VERSION 5.7 ;
BUSBITCHARS "[]" ;
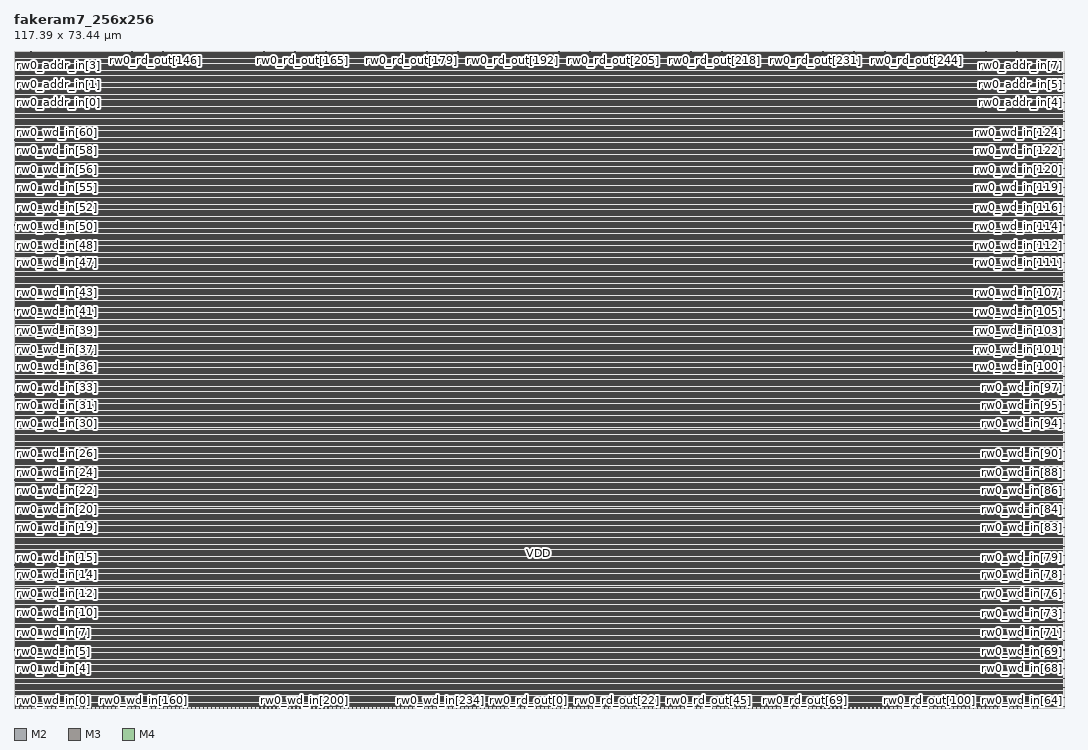
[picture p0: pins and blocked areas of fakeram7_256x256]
MACRO fakeram7_256x256
  FOREIGN fakeram7_256x256 0 0 ;
  SYMMETRY X Y R90 ;
  SIZE 117.390 BY 73.440 ;
  CLASS BLOCK ;
  PIN rw0_wd_in[0]
    DIRECTION INPUT ;
    USE SIGNAL ;
    SHAPE ABUTMENT ;
    PORT
      LAYER M2 ;
      RECT 0.000 0.138 0.036 0.150 ;
    END
  END rw0_wd_in[0]
  PIN rw0_wd_in[1]
    DIRECTION INPUT ;
    USE SIGNAL ;
    SHAPE ABUTMENT ;
    PORT
      LAYER M2 ;
      RECT 0.000 1.194 0.036 1.206 ;
    END
  END rw0_wd_in[1]
  PIN rw0_wd_in[2]
    DIRECTION INPUT ;
    USE SIGNAL ;
    SHAPE ABUTMENT ;
    PORT
      LAYER M2 ;
      RECT 0.000 2.250 0.036 2.262 ;
    END
  END rw0_wd_in[2]
  PIN rw0_wd_in[3]
    DIRECTION INPUT ;
    USE SIGNAL ;
    SHAPE ABUTMENT ;
    PORT
      LAYER M2 ;
      RECT 0.000 3.306 0.036 3.318 ;
    END
  END rw0_wd_in[3]
  PIN rw0_wd_in[4]
    DIRECTION INPUT ;
    USE SIGNAL ;
    SHAPE ABUTMENT ;
    PORT
      LAYER M2 ;
      RECT 0.000 4.362 0.036 4.374 ;
    END
  END rw0_wd_in[4]
  PIN rw0_wd_in[5]
    DIRECTION INPUT ;
    USE SIGNAL ;
    SHAPE ABUTMENT ;
    PORT
      LAYER M2 ;
      RECT 0.000 5.418 0.036 5.430 ;
    END
  END rw0_wd_in[5]
  PIN rw0_wd_in[6]
    DIRECTION INPUT ;
    USE SIGNAL ;
    SHAPE ABUTMENT ;
    PORT
      LAYER M2 ;
      RECT 0.000 6.474 0.036 6.486 ;
    END
  END rw0_wd_in[6]
  PIN rw0_wd_in[7]
    DIRECTION INPUT ;
    USE SIGNAL ;
    SHAPE ABUTMENT ;
    PORT
      LAYER M2 ;
      RECT 0.000 7.530 0.036 7.542 ;
    END
  END rw0_wd_in[7]
  PIN rw0_wd_in[8]
    DIRECTION INPUT ;
    USE SIGNAL ;
    SHAPE ABUTMENT ;
    PORT
      LAYER M2 ;
      RECT 0.000 8.586 0.036 8.598 ;
    END
  END rw0_wd_in[8]
  PIN rw0_wd_in[9]
    DIRECTION INPUT ;
    USE SIGNAL ;
    SHAPE ABUTMENT ;
    PORT
      LAYER M2 ;
      RECT 0.000 9.642 0.036 9.654 ;
    END
  END rw0_wd_in[9]
  PIN rw0_wd_in[10]
    DIRECTION INPUT ;
    USE SIGNAL ;
    SHAPE ABUTMENT ;
    PORT
      LAYER M2 ;
      RECT 0.000 10.698 0.036 10.710 ;
    END
  END rw0_wd_in[10]
  PIN rw0_wd_in[11]
    DIRECTION INPUT ;
    USE SIGNAL ;
    SHAPE ABUTMENT ;
    PORT
      LAYER M2 ;
      RECT 0.000 11.754 0.036 11.766 ;
    END
  END rw0_wd_in[11]
  PIN rw0_wd_in[12]
    DIRECTION INPUT ;
    USE SIGNAL ;
    SHAPE ABUTMENT ;
    PORT
      LAYER M2 ;
      RECT 0.000 12.810 0.036 12.822 ;
    END
  END rw0_wd_in[12]
  PIN rw0_wd_in[13]
    DIRECTION INPUT ;
    USE SIGNAL ;
    SHAPE ABUTMENT ;
    PORT
      LAYER M2 ;
      RECT 0.000 13.866 0.036 13.878 ;
    END
  END rw0_wd_in[13]
  PIN rw0_wd_in[14]
    DIRECTION INPUT ;
    USE SIGNAL ;
    SHAPE ABUTMENT ;
    PORT
      LAYER M2 ;
      RECT 0.000 14.922 0.036 14.934 ;
    END
  END rw0_wd_in[14]
  PIN rw0_wd_in[15]
    DIRECTION INPUT ;
    USE SIGNAL ;
    SHAPE ABUTMENT ;
    PORT
      LAYER M2 ;
      RECT 0.000 15.978 0.036 15.990 ;
    END
  END rw0_wd_in[15]
  PIN rw0_wd_in[16]
    DIRECTION INPUT ;
    USE SIGNAL ;
    SHAPE ABUTMENT ;
    PORT
      LAYER M2 ;
      RECT 0.000 17.034 0.036 17.046 ;
    END
  END rw0_wd_in[16]
  PIN rw0_wd_in[17]
    DIRECTION INPUT ;
    USE SIGNAL ;
    SHAPE ABUTMENT ;
    PORT
      LAYER M2 ;
      RECT 0.000 18.090 0.036 18.102 ;
    END
  END rw0_wd_in[17]
  PIN rw0_wd_in[18]
    DIRECTION INPUT ;
    USE SIGNAL ;
    SHAPE ABUTMENT ;
    PORT
      LAYER M2 ;
      RECT 0.000 19.146 0.036 19.158 ;
    END
  END rw0_wd_in[18]
  PIN rw0_wd_in[19]
    DIRECTION INPUT ;
    USE SIGNAL ;
    SHAPE ABUTMENT ;
    PORT
      LAYER M2 ;
      RECT 0.000 20.202 0.036 20.214 ;
    END
  END rw0_wd_in[19]
  PIN rw0_wd_in[20]
    DIRECTION INPUT ;
    USE SIGNAL ;
    SHAPE ABUTMENT ;
    PORT
      LAYER M2 ;
      RECT 0.000 21.258 0.036 21.270 ;
    END
  END rw0_wd_in[20]
  PIN rw0_wd_in[21]
    DIRECTION INPUT ;
    USE SIGNAL ;
    SHAPE ABUTMENT ;
    PORT
      LAYER M2 ;
      RECT 0.000 22.314 0.036 22.326 ;
    END
  END rw0_wd_in[21]
  PIN rw0_wd_in[22]
    DIRECTION INPUT ;
    USE SIGNAL ;
    SHAPE ABUTMENT ;
    PORT
      LAYER M2 ;
      RECT 0.000 23.370 0.036 23.382 ;
    END
  END rw0_wd_in[22]
  PIN rw0_wd_in[23]
    DIRECTION INPUT ;
    USE SIGNAL ;
    SHAPE ABUTMENT ;
    PORT
      LAYER M2 ;
      RECT 0.000 24.426 0.036 24.438 ;
    END
  END rw0_wd_in[23]
  PIN rw0_wd_in[24]
    DIRECTION INPUT ;
    USE SIGNAL ;
    SHAPE ABUTMENT ;
    PORT
      LAYER M2 ;
      RECT 0.000 25.482 0.036 25.494 ;
    END
  END rw0_wd_in[24]
  PIN rw0_wd_in[25]
    DIRECTION INPUT ;
    USE SIGNAL ;
    SHAPE ABUTMENT ;
    PORT
      LAYER M2 ;
      RECT 0.000 26.538 0.036 26.550 ;
    END
  END rw0_wd_in[25]
  PIN rw0_wd_in[26]
    DIRECTION INPUT ;
    USE SIGNAL ;
    SHAPE ABUTMENT ;
    PORT
      LAYER M2 ;
      RECT 0.000 27.594 0.036 27.606 ;
    END
  END rw0_wd_in[26]
  PIN rw0_wd_in[27]
    DIRECTION INPUT ;
    USE SIGNAL ;
    SHAPE ABUTMENT ;
    PORT
      LAYER M2 ;
      RECT 0.000 28.650 0.036 28.662 ;
    END
  END rw0_wd_in[27]
  PIN rw0_wd_in[28]
    DIRECTION INPUT ;
    USE SIGNAL ;
    SHAPE ABUTMENT ;
    PORT
      LAYER M2 ;
      RECT 0.000 29.706 0.036 29.718 ;
    END
  END rw0_wd_in[28]
  PIN rw0_wd_in[29]
    DIRECTION INPUT ;
    USE SIGNAL ;
    SHAPE ABUTMENT ;
    PORT
      LAYER M2 ;
      RECT 0.000 30.762 0.036 30.774 ;
    END
  END rw0_wd_in[29]
  PIN rw0_wd_in[30]
    DIRECTION INPUT ;
    USE SIGNAL ;
    SHAPE ABUTMENT ;
    PORT
      LAYER M2 ;
      RECT 0.000 31.818 0.036 31.830 ;
    END
  END rw0_wd_in[30]
  PIN rw0_wd_in[31]
    DIRECTION INPUT ;
    USE SIGNAL ;
    SHAPE ABUTMENT ;
    PORT
      LAYER M2 ;
      RECT 0.000 32.874 0.036 32.886 ;
    END
  END rw0_wd_in[31]
  PIN rw0_wd_in[32]
    DIRECTION INPUT ;
    USE SIGNAL ;
    SHAPE ABUTMENT ;
    PORT
      LAYER M2 ;
      RECT 0.000 33.930 0.036 33.942 ;
    END
  END rw0_wd_in[32]
  PIN rw0_wd_in[33]
    DIRECTION INPUT ;
    USE SIGNAL ;
    SHAPE ABUTMENT ;
    PORT
      LAYER M2 ;
      RECT 0.000 34.986 0.036 34.998 ;
    END
  END rw0_wd_in[33]
  PIN rw0_wd_in[34]
    DIRECTION INPUT ;
    USE SIGNAL ;
    SHAPE ABUTMENT ;
    PORT
      LAYER M2 ;
      RECT 0.000 36.042 0.036 36.054 ;
    END
  END rw0_wd_in[34]
  PIN rw0_wd_in[35]
    DIRECTION INPUT ;
    USE SIGNAL ;
    SHAPE ABUTMENT ;
    PORT
      LAYER M2 ;
      RECT 0.000 37.098 0.036 37.110 ;
    END
  END rw0_wd_in[35]
  PIN rw0_wd_in[36]
    DIRECTION INPUT ;
    USE SIGNAL ;
    SHAPE ABUTMENT ;
    PORT
      LAYER M2 ;
      RECT 0.000 38.154 0.036 38.166 ;
    END
  END rw0_wd_in[36]
  PIN rw0_wd_in[37]
    DIRECTION INPUT ;
    USE SIGNAL ;
    SHAPE ABUTMENT ;
    PORT
      LAYER M2 ;
      RECT 0.000 39.210 0.036 39.222 ;
    END
  END rw0_wd_in[37]
  PIN rw0_wd_in[38]
    DIRECTION INPUT ;
    USE SIGNAL ;
    SHAPE ABUTMENT ;
    PORT
      LAYER M2 ;
      RECT 0.000 40.266 0.036 40.278 ;
    END
  END rw0_wd_in[38]
  PIN rw0_wd_in[39]
    DIRECTION INPUT ;
    USE SIGNAL ;
    SHAPE ABUTMENT ;
    PORT
      LAYER M2 ;
      RECT 0.000 41.322 0.036 41.334 ;
    END
  END rw0_wd_in[39]
  PIN rw0_wd_in[40]
    DIRECTION INPUT ;
    USE SIGNAL ;
    SHAPE ABUTMENT ;
    PORT
      LAYER M2 ;
      RECT 0.000 42.378 0.036 42.390 ;
    END
  END rw0_wd_in[40]
  PIN rw0_wd_in[41]
    DIRECTION INPUT ;
    USE SIGNAL ;
    SHAPE ABUTMENT ;
    PORT
      LAYER M2 ;
      RECT 0.000 43.434 0.036 43.446 ;
    END
  END rw0_wd_in[41]
  PIN rw0_wd_in[42]
    DIRECTION INPUT ;
    USE SIGNAL ;
    SHAPE ABUTMENT ;
    PORT
      LAYER M2 ;
      RECT 0.000 44.490 0.036 44.502 ;
    END
  END rw0_wd_in[42]
  PIN rw0_wd_in[43]
    DIRECTION INPUT ;
    USE SIGNAL ;
    SHAPE ABUTMENT ;
    PORT
      LAYER M2 ;
      RECT 0.000 45.546 0.036 45.558 ;
    END
  END rw0_wd_in[43]
  PIN rw0_wd_in[44]
    DIRECTION INPUT ;
    USE SIGNAL ;
    SHAPE ABUTMENT ;
    PORT
      LAYER M2 ;
      RECT 0.000 46.602 0.036 46.614 ;
    END
  END rw0_wd_in[44]
  PIN rw0_wd_in[45]
    DIRECTION INPUT ;
    USE SIGNAL ;
    SHAPE ABUTMENT ;
    PORT
      LAYER M2 ;
      RECT 0.000 47.658 0.036 47.670 ;
    END
  END rw0_wd_in[45]
  PIN rw0_wd_in[46]
    DIRECTION INPUT ;
    USE SIGNAL ;
    SHAPE ABUTMENT ;
    PORT
      LAYER M2 ;
      RECT 0.000 48.714 0.036 48.726 ;
    END
  END rw0_wd_in[46]
  PIN rw0_wd_in[47]
    DIRECTION INPUT ;
    USE SIGNAL ;
    SHAPE ABUTMENT ;
    PORT
      LAYER M2 ;
      RECT 0.000 49.770 0.036 49.782 ;
    END
  END rw0_wd_in[47]
  PIN rw0_wd_in[48]
    DIRECTION INPUT ;
    USE SIGNAL ;
    SHAPE ABUTMENT ;
    PORT
      LAYER M2 ;
      RECT 0.000 50.826 0.036 50.838 ;
    END
  END rw0_wd_in[48]
  PIN rw0_wd_in[49]
    DIRECTION INPUT ;
    USE SIGNAL ;
    SHAPE ABUTMENT ;
    PORT
      LAYER M2 ;
      RECT 0.000 51.882 0.036 51.894 ;
    END
  END rw0_wd_in[49]
  PIN rw0_wd_in[50]
    DIRECTION INPUT ;
    USE SIGNAL ;
    SHAPE ABUTMENT ;
    PORT
      LAYER M2 ;
      RECT 0.000 52.938 0.036 52.950 ;
    END
  END rw0_wd_in[50]
  PIN rw0_wd_in[51]
    DIRECTION INPUT ;
    USE SIGNAL ;
    SHAPE ABUTMENT ;
    PORT
      LAYER M2 ;
      RECT 0.000 53.994 0.036 54.006 ;
    END
  END rw0_wd_in[51]
  PIN rw0_wd_in[52]
    DIRECTION INPUT ;
    USE SIGNAL ;
    SHAPE ABUTMENT ;
    PORT
      LAYER M2 ;
      RECT 0.000 55.050 0.036 55.062 ;
    END
  END rw0_wd_in[52]
  PIN rw0_wd_in[53]
    DIRECTION INPUT ;
    USE SIGNAL ;
    SHAPE ABUTMENT ;
    PORT
      LAYER M2 ;
      RECT 0.000 56.106 0.036 56.118 ;
    END
  END rw0_wd_in[53]
  PIN rw0_wd_in[54]
    DIRECTION INPUT ;
    USE SIGNAL ;
    SHAPE ABUTMENT ;
    PORT
      LAYER M2 ;
      RECT 0.000 57.162 0.036 57.174 ;
    END
  END rw0_wd_in[54]
  PIN rw0_wd_in[55]
    DIRECTION INPUT ;
    USE SIGNAL ;
    SHAPE ABUTMENT ;
    PORT
      LAYER M2 ;
      RECT 0.000 58.218 0.036 58.230 ;
    END
  END rw0_wd_in[55]
  PIN rw0_wd_in[56]
    DIRECTION INPUT ;
    USE SIGNAL ;
    SHAPE ABUTMENT ;
    PORT
      LAYER M2 ;
      RECT 0.000 59.274 0.036 59.286 ;
    END
  END rw0_wd_in[56]
  PIN rw0_wd_in[57]
    DIRECTION INPUT ;
    USE SIGNAL ;
    SHAPE ABUTMENT ;
    PORT
      LAYER M2 ;
      RECT 0.000 60.330 0.036 60.342 ;
    END
  END rw0_wd_in[57]
  PIN rw0_wd_in[58]
    DIRECTION INPUT ;
    USE SIGNAL ;
    SHAPE ABUTMENT ;
    PORT
      LAYER M2 ;
      RECT 0.000 61.386 0.036 61.398 ;
    END
  END rw0_wd_in[58]
  PIN rw0_wd_in[59]
    DIRECTION INPUT ;
    USE SIGNAL ;
    SHAPE ABUTMENT ;
    PORT
      LAYER M2 ;
      RECT 0.000 62.442 0.036 62.454 ;
    END
  END rw0_wd_in[59]
  PIN rw0_wd_in[60]
    DIRECTION INPUT ;
    USE SIGNAL ;
    SHAPE ABUTMENT ;
    PORT
      LAYER M2 ;
      RECT 0.000 63.498 0.036 63.510 ;
    END
  END rw0_wd_in[60]
  PIN rw0_wd_in[61]
    DIRECTION INPUT ;
    USE SIGNAL ;
    SHAPE ABUTMENT ;
    PORT
      LAYER M2 ;
      RECT 0.000 64.554 0.036 64.566 ;
    END
  END rw0_wd_in[61]
  PIN rw0_wd_in[62]
    DIRECTION INPUT ;
    USE SIGNAL ;
    SHAPE ABUTMENT ;
    PORT
      LAYER M2 ;
      RECT 0.000 65.610 0.036 65.622 ;
    END
  END rw0_wd_in[62]
  PIN rw0_wd_in[63]
    DIRECTION INPUT ;
    USE SIGNAL ;
    SHAPE ABUTMENT ;
    PORT
      LAYER M2 ;
      RECT 0.000 66.666 0.036 66.678 ;
    END
  END rw0_wd_in[63]
  PIN rw0_wd_in[64]
    DIRECTION INPUT ;
    USE SIGNAL ;
    SHAPE ABUTMENT ;
    PORT
      LAYER M2 ;
      RECT 117.354 0.138 117.390 0.150 ;
    END
  END rw0_wd_in[64]
  PIN rw0_wd_in[65]
    DIRECTION INPUT ;
    USE SIGNAL ;
    SHAPE ABUTMENT ;
    PORT
      LAYER M2 ;
      RECT 117.354 1.194 117.390 1.206 ;
    END
  END rw0_wd_in[65]
  PIN rw0_wd_in[66]
    DIRECTION INPUT ;
    USE SIGNAL ;
    SHAPE ABUTMENT ;
    PORT
      LAYER M2 ;
      RECT 117.354 2.250 117.390 2.262 ;
    END
  END rw0_wd_in[66]
  PIN rw0_wd_in[67]
    DIRECTION INPUT ;
    USE SIGNAL ;
    SHAPE ABUTMENT ;
    PORT
      LAYER M2 ;
      RECT 117.354 3.306 117.390 3.318 ;
    END
  END rw0_wd_in[67]
  PIN rw0_wd_in[68]
    DIRECTION INPUT ;
    USE SIGNAL ;
    SHAPE ABUTMENT ;
    PORT
      LAYER M2 ;
      RECT 117.354 4.362 117.390 4.374 ;
    END
  END rw0_wd_in[68]
  PIN rw0_wd_in[69]
    DIRECTION INPUT ;
    USE SIGNAL ;
    SHAPE ABUTMENT ;
    PORT
      LAYER M2 ;
      RECT 117.354 5.418 117.390 5.430 ;
    END
  END rw0_wd_in[69]
  PIN rw0_wd_in[70]
    DIRECTION INPUT ;
    USE SIGNAL ;
    SHAPE ABUTMENT ;
    PORT
      LAYER M2 ;
      RECT 117.354 6.474 117.390 6.486 ;
    END
  END rw0_wd_in[70]
  PIN rw0_wd_in[71]
    DIRECTION INPUT ;
    USE SIGNAL ;
    SHAPE ABUTMENT ;
    PORT
      LAYER M2 ;
      RECT 117.354 7.530 117.390 7.542 ;
    END
  END rw0_wd_in[71]
  PIN rw0_wd_in[72]
    DIRECTION INPUT ;
    USE SIGNAL ;
    SHAPE ABUTMENT ;
    PORT
      LAYER M2 ;
      RECT 117.354 8.586 117.390 8.598 ;
    END
  END rw0_wd_in[72]
  PIN rw0_wd_in[73]
    DIRECTION INPUT ;
    USE SIGNAL ;
    SHAPE ABUTMENT ;
    PORT
      LAYER M2 ;
      RECT 117.354 9.642 117.390 9.654 ;
    END
  END rw0_wd_in[73]
  PIN rw0_wd_in[74]
    DIRECTION INPUT ;
    USE SIGNAL ;
    SHAPE ABUTMENT ;
    PORT
      LAYER M2 ;
      RECT 117.354 10.698 117.390 10.710 ;
    END
  END rw0_wd_in[74]
  PIN rw0_wd_in[75]
    DIRECTION INPUT ;
    USE SIGNAL ;
    SHAPE ABUTMENT ;
    PORT
      LAYER M2 ;
      RECT 117.354 11.754 117.390 11.766 ;
    END
  END rw0_wd_in[75]
  PIN rw0_wd_in[76]
    DIRECTION INPUT ;
    USE SIGNAL ;
    SHAPE ABUTMENT ;
    PORT
      LAYER M2 ;
      RECT 117.354 12.810 117.390 12.822 ;
    END
  END rw0_wd_in[76]
  PIN rw0_wd_in[77]
    DIRECTION INPUT ;
    USE SIGNAL ;
    SHAPE ABUTMENT ;
    PORT
      LAYER M2 ;
      RECT 117.354 13.866 117.390 13.878 ;
    END
  END rw0_wd_in[77]
  PIN rw0_wd_in[78]
    DIRECTION INPUT ;
    USE SIGNAL ;
    SHAPE ABUTMENT ;
    PORT
      LAYER M2 ;
      RECT 117.354 14.922 117.390 14.934 ;
    END
  END rw0_wd_in[78]
  PIN rw0_wd_in[79]
    DIRECTION INPUT ;
    USE SIGNAL ;
    SHAPE ABUTMENT ;
    PORT
      LAYER M2 ;
      RECT 117.354 15.978 117.390 15.990 ;
    END
  END rw0_wd_in[79]
  PIN rw0_wd_in[80]
    DIRECTION INPUT ;
    USE SIGNAL ;
    SHAPE ABUTMENT ;
    PORT
      LAYER M2 ;
      RECT 117.354 17.034 117.390 17.046 ;
    END
  END rw0_wd_in[80]
  PIN rw0_wd_in[81]
    DIRECTION INPUT ;
    USE SIGNAL ;
    SHAPE ABUTMENT ;
    PORT
      LAYER M2 ;
      RECT 117.354 18.090 117.390 18.102 ;
    END
  END rw0_wd_in[81]
  PIN rw0_wd_in[82]
    DIRECTION INPUT ;
    USE SIGNAL ;
    SHAPE ABUTMENT ;
    PORT
      LAYER M2 ;
      RECT 117.354 19.146 117.390 19.158 ;
    END
  END rw0_wd_in[82]
  PIN rw0_wd_in[83]
    DIRECTION INPUT ;
    USE SIGNAL ;
    SHAPE ABUTMENT ;
    PORT
      LAYER M2 ;
      RECT 117.354 20.202 117.390 20.214 ;
    END
  END rw0_wd_in[83]
  PIN rw0_wd_in[84]
    DIRECTION INPUT ;
    USE SIGNAL ;
    SHAPE ABUTMENT ;
    PORT
      LAYER M2 ;
      RECT 117.354 21.258 117.390 21.270 ;
    END
  END rw0_wd_in[84]
  PIN rw0_wd_in[85]
    DIRECTION INPUT ;
    USE SIGNAL ;
    SHAPE ABUTMENT ;
    PORT
      LAYER M2 ;
      RECT 117.354 22.314 117.390 22.326 ;
    END
  END rw0_wd_in[85]
  PIN rw0_wd_in[86]
    DIRECTION INPUT ;
    USE SIGNAL ;
    SHAPE ABUTMENT ;
    PORT
      LAYER M2 ;
      RECT 117.354 23.370 117.390 23.382 ;
    END
  END rw0_wd_in[86]
  PIN rw0_wd_in[87]
    DIRECTION INPUT ;
    USE SIGNAL ;
    SHAPE ABUTMENT ;
    PORT
      LAYER M2 ;
      RECT 117.354 24.426 117.390 24.438 ;
    END
  END rw0_wd_in[87]
  PIN rw0_wd_in[88]
    DIRECTION INPUT ;
    USE SIGNAL ;
    SHAPE ABUTMENT ;
    PORT
      LAYER M2 ;
      RECT 117.354 25.482 117.390 25.494 ;
    END
  END rw0_wd_in[88]
  PIN rw0_wd_in[89]
    DIRECTION INPUT ;
    USE SIGNAL ;
    SHAPE ABUTMENT ;
    PORT
      LAYER M2 ;
      RECT 117.354 26.538 117.390 26.550 ;
    END
  END rw0_wd_in[89]
  PIN rw0_wd_in[90]
    DIRECTION INPUT ;
    USE SIGNAL ;
    SHAPE ABUTMENT ;
    PORT
      LAYER M2 ;
      RECT 117.354 27.594 117.390 27.606 ;
    END
  END rw0_wd_in[90]
  PIN rw0_wd_in[91]
    DIRECTION INPUT ;
    USE SIGNAL ;
    SHAPE ABUTMENT ;
    PORT
      LAYER M2 ;
      RECT 117.354 28.650 117.390 28.662 ;
    END
  END rw0_wd_in[91]
  PIN rw0_wd_in[92]
    DIRECTION INPUT ;
    USE SIGNAL ;
    SHAPE ABUTMENT ;
    PORT
      LAYER M2 ;
      RECT 117.354 29.706 117.390 29.718 ;
    END
  END rw0_wd_in[92]
  PIN rw0_wd_in[93]
    DIRECTION INPUT ;
    USE SIGNAL ;
    SHAPE ABUTMENT ;
    PORT
      LAYER M2 ;
      RECT 117.354 30.762 117.390 30.774 ;
    END
  END rw0_wd_in[93]
  PIN rw0_wd_in[94]
    DIRECTION INPUT ;
    USE SIGNAL ;
    SHAPE ABUTMENT ;
    PORT
      LAYER M2 ;
      RECT 117.354 31.818 117.390 31.830 ;
    END
  END rw0_wd_in[94]
  PIN rw0_wd_in[95]
    DIRECTION INPUT ;
    USE SIGNAL ;
    SHAPE ABUTMENT ;
    PORT
      LAYER M2 ;
      RECT 117.354 32.874 117.390 32.886 ;
    END
  END rw0_wd_in[95]
  PIN rw0_wd_in[96]
    DIRECTION INPUT ;
    USE SIGNAL ;
    SHAPE ABUTMENT ;
    PORT
      LAYER M2 ;
      RECT 117.354 33.930 117.390 33.942 ;
    END
  END rw0_wd_in[96]
  PIN rw0_wd_in[97]
    DIRECTION INPUT ;
    USE SIGNAL ;
    SHAPE ABUTMENT ;
    PORT
      LAYER M2 ;
      RECT 117.354 34.986 117.390 34.998 ;
    END
  END rw0_wd_in[97]
  PIN rw0_wd_in[98]
    DIRECTION INPUT ;
    USE SIGNAL ;
    SHAPE ABUTMENT ;
    PORT
      LAYER M2 ;
      RECT 117.354 36.042 117.390 36.054 ;
    END
  END rw0_wd_in[98]
  PIN rw0_wd_in[99]
    DIRECTION INPUT ;
    USE SIGNAL ;
    SHAPE ABUTMENT ;
    PORT
      LAYER M2 ;
      RECT 117.354 37.098 117.390 37.110 ;
    END
  END rw0_wd_in[99]
  PIN rw0_wd_in[100]
    DIRECTION INPUT ;
    USE SIGNAL ;
    SHAPE ABUTMENT ;
    PORT
      LAYER M2 ;
      RECT 117.354 38.154 117.390 38.166 ;
    END
  END rw0_wd_in[100]
  PIN rw0_wd_in[101]
    DIRECTION INPUT ;
    USE SIGNAL ;
    SHAPE ABUTMENT ;
    PORT
      LAYER M2 ;
      RECT 117.354 39.210 117.390 39.222 ;
    END
  END rw0_wd_in[101]
  PIN rw0_wd_in[102]
    DIRECTION INPUT ;
    USE SIGNAL ;
    SHAPE ABUTMENT ;
    PORT
      LAYER M2 ;
      RECT 117.354 40.266 117.390 40.278 ;
    END
  END rw0_wd_in[102]
  PIN rw0_wd_in[103]
    DIRECTION INPUT ;
    USE SIGNAL ;
    SHAPE ABUTMENT ;
    PORT
      LAYER M2 ;
      RECT 117.354 41.322 117.390 41.334 ;
    END
  END rw0_wd_in[103]
  PIN rw0_wd_in[104]
    DIRECTION INPUT ;
    USE SIGNAL ;
    SHAPE ABUTMENT ;
    PORT
      LAYER M2 ;
      RECT 117.354 42.378 117.390 42.390 ;
    END
  END rw0_wd_in[104]
  PIN rw0_wd_in[105]
    DIRECTION INPUT ;
    USE SIGNAL ;
    SHAPE ABUTMENT ;
    PORT
      LAYER M2 ;
      RECT 117.354 43.434 117.390 43.446 ;
    END
  END rw0_wd_in[105]
  PIN rw0_wd_in[106]
    DIRECTION INPUT ;
    USE SIGNAL ;
    SHAPE ABUTMENT ;
    PORT
      LAYER M2 ;
      RECT 117.354 44.490 117.390 44.502 ;
    END
  END rw0_wd_in[106]
  PIN rw0_wd_in[107]
    DIRECTION INPUT ;
    USE SIGNAL ;
    SHAPE ABUTMENT ;
    PORT
      LAYER M2 ;
      RECT 117.354 45.546 117.390 45.558 ;
    END
  END rw0_wd_in[107]
  PIN rw0_wd_in[108]
    DIRECTION INPUT ;
    USE SIGNAL ;
    SHAPE ABUTMENT ;
    PORT
      LAYER M2 ;
      RECT 117.354 46.602 117.390 46.614 ;
    END
  END rw0_wd_in[108]
  PIN rw0_wd_in[109]
    DIRECTION INPUT ;
    USE SIGNAL ;
    SHAPE ABUTMENT ;
    PORT
      LAYER M2 ;
      RECT 117.354 47.658 117.390 47.670 ;
    END
  END rw0_wd_in[109]
  PIN rw0_wd_in[110]
    DIRECTION INPUT ;
    USE SIGNAL ;
    SHAPE ABUTMENT ;
    PORT
      LAYER M2 ;
      RECT 117.354 48.714 117.390 48.726 ;
    END
  END rw0_wd_in[110]
  PIN rw0_wd_in[111]
    DIRECTION INPUT ;
    USE SIGNAL ;
    SHAPE ABUTMENT ;
    PORT
      LAYER M2 ;
      RECT 117.354 49.770 117.390 49.782 ;
    END
  END rw0_wd_in[111]
  PIN rw0_wd_in[112]
    DIRECTION INPUT ;
    USE SIGNAL ;
    SHAPE ABUTMENT ;
    PORT
      LAYER M2 ;
      RECT 117.354 50.826 117.390 50.838 ;
    END
  END rw0_wd_in[112]
  PIN rw0_wd_in[113]
    DIRECTION INPUT ;
    USE SIGNAL ;
    SHAPE ABUTMENT ;
    PORT
      LAYER M2 ;
      RECT 117.354 51.882 117.390 51.894 ;
    END
  END rw0_wd_in[113]
  PIN rw0_wd_in[114]
    DIRECTION INPUT ;
    USE SIGNAL ;
    SHAPE ABUTMENT ;
    PORT
      LAYER M2 ;
      RECT 117.354 52.938 117.390 52.950 ;
    END
  END rw0_wd_in[114]
  PIN rw0_wd_in[115]
    DIRECTION INPUT ;
    USE SIGNAL ;
    SHAPE ABUTMENT ;
    PORT
      LAYER M2 ;
      RECT 117.354 53.994 117.390 54.006 ;
    END
  END rw0_wd_in[115]
  PIN rw0_wd_in[116]
    DIRECTION INPUT ;
    USE SIGNAL ;
    SHAPE ABUTMENT ;
    PORT
      LAYER M2 ;
      RECT 117.354 55.050 117.390 55.062 ;
    END
  END rw0_wd_in[116]
  PIN rw0_wd_in[117]
    DIRECTION INPUT ;
    USE SIGNAL ;
    SHAPE ABUTMENT ;
    PORT
      LAYER M2 ;
      RECT 117.354 56.106 117.390 56.118 ;
    END
  END rw0_wd_in[117]
  PIN rw0_wd_in[118]
    DIRECTION INPUT ;
    USE SIGNAL ;
    SHAPE ABUTMENT ;
    PORT
      LAYER M2 ;
      RECT 117.354 57.162 117.390 57.174 ;
    END
  END rw0_wd_in[118]
  PIN rw0_wd_in[119]
    DIRECTION INPUT ;
    USE SIGNAL ;
    SHAPE ABUTMENT ;
    PORT
      LAYER M2 ;
      RECT 117.354 58.218 117.390 58.230 ;
    END
  END rw0_wd_in[119]
  PIN rw0_wd_in[120]
    DIRECTION INPUT ;
    USE SIGNAL ;
    SHAPE ABUTMENT ;
    PORT
      LAYER M2 ;
      RECT 117.354 59.274 117.390 59.286 ;
    END
  END rw0_wd_in[120]
  PIN rw0_wd_in[121]
    DIRECTION INPUT ;
    USE SIGNAL ;
    SHAPE ABUTMENT ;
    PORT
      LAYER M2 ;
      RECT 117.354 60.330 117.390 60.342 ;
    END
  END rw0_wd_in[121]
  PIN rw0_wd_in[122]
    DIRECTION INPUT ;
    USE SIGNAL ;
    SHAPE ABUTMENT ;
    PORT
      LAYER M2 ;
      RECT 117.354 61.386 117.390 61.398 ;
    END
  END rw0_wd_in[122]
  PIN rw0_wd_in[123]
    DIRECTION INPUT ;
    USE SIGNAL ;
    SHAPE ABUTMENT ;
    PORT
      LAYER M2 ;
      RECT 117.354 62.442 117.390 62.454 ;
    END
  END rw0_wd_in[123]
  PIN rw0_wd_in[124]
    DIRECTION INPUT ;
    USE SIGNAL ;
    SHAPE ABUTMENT ;
    PORT
      LAYER M2 ;
      RECT 117.354 63.498 117.390 63.510 ;
    END
  END rw0_wd_in[124]
  PIN rw0_wd_in[125]
    DIRECTION INPUT ;
    USE SIGNAL ;
    SHAPE ABUTMENT ;
    PORT
      LAYER M2 ;
      RECT 117.354 64.554 117.390 64.566 ;
    END
  END rw0_wd_in[125]
  PIN rw0_wd_in[126]
    DIRECTION INPUT ;
    USE SIGNAL ;
    SHAPE ABUTMENT ;
    PORT
      LAYER M2 ;
      RECT 117.354 65.610 117.390 65.622 ;
    END
  END rw0_wd_in[126]
  PIN rw0_wd_in[127]
    DIRECTION INPUT ;
    USE SIGNAL ;
    SHAPE ABUTMENT ;
    PORT
      LAYER M2 ;
      RECT 117.354 66.666 117.390 66.678 ;
    END
  END rw0_wd_in[127]
  PIN rw0_wd_in[128]
    DIRECTION INPUT ;
    USE SIGNAL ;
    SHAPE ABUTMENT ;
    PORT
      LAYER M3 ;
      RECT 0.161 0.000 0.175 0.042 ;
    END
  END rw0_wd_in[128]
  PIN rw0_wd_in[129]
    DIRECTION INPUT ;
    USE SIGNAL ;
    SHAPE ABUTMENT ;
    PORT
      LAYER M3 ;
      RECT 0.609 0.000 0.623 0.042 ;
    END
  END rw0_wd_in[129]
  PIN rw0_wd_in[130]
    DIRECTION INPUT ;
    USE SIGNAL ;
    SHAPE ABUTMENT ;
    PORT
      LAYER M3 ;
      RECT 1.057 0.000 1.071 0.042 ;
    END
  END rw0_wd_in[130]
  PIN rw0_wd_in[131]
    DIRECTION INPUT ;
    USE SIGNAL ;
    SHAPE ABUTMENT ;
    PORT
      LAYER M3 ;
      RECT 1.505 0.000 1.519 0.042 ;
    END
  END rw0_wd_in[131]
  PIN rw0_wd_in[132]
    DIRECTION INPUT ;
    USE SIGNAL ;
    SHAPE ABUTMENT ;
    PORT
      LAYER M3 ;
      RECT 1.953 0.000 1.967 0.042 ;
    END
  END rw0_wd_in[132]
  PIN rw0_wd_in[133]
    DIRECTION INPUT ;
    USE SIGNAL ;
    SHAPE ABUTMENT ;
    PORT
      LAYER M3 ;
      RECT 2.401 0.000 2.415 0.042 ;
    END
  END rw0_wd_in[133]
  PIN rw0_wd_in[134]
    DIRECTION INPUT ;
    USE SIGNAL ;
    SHAPE ABUTMENT ;
    PORT
      LAYER M3 ;
      RECT 2.849 0.000 2.863 0.042 ;
    END
  END rw0_wd_in[134]
  PIN rw0_wd_in[135]
    DIRECTION INPUT ;
    USE SIGNAL ;
    SHAPE ABUTMENT ;
    PORT
      LAYER M3 ;
      RECT 3.297 0.000 3.311 0.042 ;
    END
  END rw0_wd_in[135]
  PIN rw0_wd_in[136]
    DIRECTION INPUT ;
    USE SIGNAL ;
    SHAPE ABUTMENT ;
    PORT
      LAYER M3 ;
      RECT 3.745 0.000 3.759 0.042 ;
    END
  END rw0_wd_in[136]
  PIN rw0_wd_in[137]
    DIRECTION INPUT ;
    USE SIGNAL ;
    SHAPE ABUTMENT ;
    PORT
      LAYER M3 ;
      RECT 4.193 0.000 4.207 0.042 ;
    END
  END rw0_wd_in[137]
  PIN rw0_wd_in[138]
    DIRECTION INPUT ;
    USE SIGNAL ;
    SHAPE ABUTMENT ;
    PORT
      LAYER M3 ;
      RECT 4.641 0.000 4.655 0.042 ;
    END
  END rw0_wd_in[138]
  PIN rw0_wd_in[139]
    DIRECTION INPUT ;
    USE SIGNAL ;
    SHAPE ABUTMENT ;
    PORT
      LAYER M3 ;
      RECT 5.089 0.000 5.103 0.042 ;
    END
  END rw0_wd_in[139]
  PIN rw0_wd_in[140]
    DIRECTION INPUT ;
    USE SIGNAL ;
    SHAPE ABUTMENT ;
    PORT
      LAYER M3 ;
      RECT 5.537 0.000 5.551 0.042 ;
    END
  END rw0_wd_in[140]
  PIN rw0_wd_in[141]
    DIRECTION INPUT ;
    USE SIGNAL ;
    SHAPE ABUTMENT ;
    PORT
      LAYER M3 ;
      RECT 5.985 0.000 5.999 0.042 ;
    END
  END rw0_wd_in[141]
  PIN rw0_wd_in[142]
    DIRECTION INPUT ;
    USE SIGNAL ;
    SHAPE ABUTMENT ;
    PORT
      LAYER M3 ;
      RECT 6.433 0.000 6.447 0.042 ;
    END
  END rw0_wd_in[142]
  PIN rw0_wd_in[143]
    DIRECTION INPUT ;
    USE SIGNAL ;
    SHAPE ABUTMENT ;
    PORT
      LAYER M3 ;
      RECT 6.881 0.000 6.895 0.042 ;
    END
  END rw0_wd_in[143]
  PIN rw0_wd_in[144]
    DIRECTION INPUT ;
    USE SIGNAL ;
    SHAPE ABUTMENT ;
    PORT
      LAYER M3 ;
      RECT 7.329 0.000 7.343 0.042 ;
    END
  END rw0_wd_in[144]
  PIN rw0_wd_in[145]
    DIRECTION INPUT ;
    USE SIGNAL ;
    SHAPE ABUTMENT ;
    PORT
      LAYER M3 ;
      RECT 7.777 0.000 7.791 0.042 ;
    END
  END rw0_wd_in[145]
  PIN rw0_wd_in[146]
    DIRECTION INPUT ;
    USE SIGNAL ;
    SHAPE ABUTMENT ;
    PORT
      LAYER M3 ;
      RECT 8.225 0.000 8.239 0.042 ;
    END
  END rw0_wd_in[146]
  PIN rw0_wd_in[147]
    DIRECTION INPUT ;
    USE SIGNAL ;
    SHAPE ABUTMENT ;
    PORT
      LAYER M3 ;
      RECT 8.673 0.000 8.687 0.042 ;
    END
  END rw0_wd_in[147]
  PIN rw0_wd_in[148]
    DIRECTION INPUT ;
    USE SIGNAL ;
    SHAPE ABUTMENT ;
    PORT
      LAYER M3 ;
      RECT 9.121 0.000 9.135 0.042 ;
    END
  END rw0_wd_in[148]
  PIN rw0_wd_in[149]
    DIRECTION INPUT ;
    USE SIGNAL ;
    SHAPE ABUTMENT ;
    PORT
      LAYER M3 ;
      RECT 9.569 0.000 9.583 0.042 ;
    END
  END rw0_wd_in[149]
  PIN rw0_wd_in[150]
    DIRECTION INPUT ;
    USE SIGNAL ;
    SHAPE ABUTMENT ;
    PORT
      LAYER M3 ;
      RECT 10.017 0.000 10.031 0.042 ;
    END
  END rw0_wd_in[150]
  PIN rw0_wd_in[151]
    DIRECTION INPUT ;
    USE SIGNAL ;
    SHAPE ABUTMENT ;
    PORT
      LAYER M3 ;
      RECT 10.465 0.000 10.479 0.042 ;
    END
  END rw0_wd_in[151]
  PIN rw0_wd_in[152]
    DIRECTION INPUT ;
    USE SIGNAL ;
    SHAPE ABUTMENT ;
    PORT
      LAYER M3 ;
      RECT 10.913 0.000 10.927 0.042 ;
    END
  END rw0_wd_in[152]
  PIN rw0_wd_in[153]
    DIRECTION INPUT ;
    USE SIGNAL ;
    SHAPE ABUTMENT ;
    PORT
      LAYER M3 ;
      RECT 11.361 0.000 11.375 0.042 ;
    END
  END rw0_wd_in[153]
  PIN rw0_wd_in[154]
    DIRECTION INPUT ;
    USE SIGNAL ;
    SHAPE ABUTMENT ;
    PORT
      LAYER M3 ;
      RECT 11.809 0.000 11.823 0.042 ;
    END
  END rw0_wd_in[154]
  PIN rw0_wd_in[155]
    DIRECTION INPUT ;
    USE SIGNAL ;
    SHAPE ABUTMENT ;
    PORT
      LAYER M3 ;
      RECT 12.257 0.000 12.271 0.042 ;
    END
  END rw0_wd_in[155]
  PIN rw0_wd_in[156]
    DIRECTION INPUT ;
    USE SIGNAL ;
    SHAPE ABUTMENT ;
    PORT
      LAYER M3 ;
      RECT 12.705 0.000 12.719 0.042 ;
    END
  END rw0_wd_in[156]
  PIN rw0_wd_in[157]
    DIRECTION INPUT ;
    USE SIGNAL ;
    SHAPE ABUTMENT ;
    PORT
      LAYER M3 ;
      RECT 13.153 0.000 13.167 0.042 ;
    END
  END rw0_wd_in[157]
  PIN rw0_wd_in[158]
    DIRECTION INPUT ;
    USE SIGNAL ;
    SHAPE ABUTMENT ;
    PORT
      LAYER M3 ;
      RECT 13.601 0.000 13.615 0.042 ;
    END
  END rw0_wd_in[158]
  PIN rw0_wd_in[159]
    DIRECTION INPUT ;
    USE SIGNAL ;
    SHAPE ABUTMENT ;
    PORT
      LAYER M3 ;
      RECT 14.049 0.000 14.063 0.042 ;
    END
  END rw0_wd_in[159]
  PIN rw0_wd_in[160]
    DIRECTION INPUT ;
    USE SIGNAL ;
    SHAPE ABUTMENT ;
    PORT
      LAYER M3 ;
      RECT 14.497 0.000 14.511 0.042 ;
    END
  END rw0_wd_in[160]
  PIN rw0_wd_in[161]
    DIRECTION INPUT ;
    USE SIGNAL ;
    SHAPE ABUTMENT ;
    PORT
      LAYER M3 ;
      RECT 14.945 0.000 14.959 0.042 ;
    END
  END rw0_wd_in[161]
  PIN rw0_wd_in[162]
    DIRECTION INPUT ;
    USE SIGNAL ;
    SHAPE ABUTMENT ;
    PORT
      LAYER M3 ;
      RECT 15.393 0.000 15.407 0.042 ;
    END
  END rw0_wd_in[162]
  PIN rw0_wd_in[163]
    DIRECTION INPUT ;
    USE SIGNAL ;
    SHAPE ABUTMENT ;
    PORT
      LAYER M3 ;
      RECT 15.841 0.000 15.855 0.042 ;
    END
  END rw0_wd_in[163]
  PIN rw0_wd_in[164]
    DIRECTION INPUT ;
    USE SIGNAL ;
    SHAPE ABUTMENT ;
    PORT
      LAYER M3 ;
      RECT 16.289 0.000 16.303 0.042 ;
    END
  END rw0_wd_in[164]
  PIN rw0_wd_in[165]
    DIRECTION INPUT ;
    USE SIGNAL ;
    SHAPE ABUTMENT ;
    PORT
      LAYER M3 ;
      RECT 16.737 0.000 16.751 0.042 ;
    END
  END rw0_wd_in[165]
  PIN rw0_wd_in[166]
    DIRECTION INPUT ;
    USE SIGNAL ;
    SHAPE ABUTMENT ;
    PORT
      LAYER M3 ;
      RECT 17.185 0.000 17.199 0.042 ;
    END
  END rw0_wd_in[166]
  PIN rw0_wd_in[167]
    DIRECTION INPUT ;
    USE SIGNAL ;
    SHAPE ABUTMENT ;
    PORT
      LAYER M3 ;
      RECT 17.633 0.000 17.647 0.042 ;
    END
  END rw0_wd_in[167]
  PIN rw0_wd_in[168]
    DIRECTION INPUT ;
    USE SIGNAL ;
    SHAPE ABUTMENT ;
    PORT
      LAYER M3 ;
      RECT 18.081 0.000 18.095 0.042 ;
    END
  END rw0_wd_in[168]
  PIN rw0_wd_in[169]
    DIRECTION INPUT ;
    USE SIGNAL ;
    SHAPE ABUTMENT ;
    PORT
      LAYER M3 ;
      RECT 18.529 0.000 18.543 0.042 ;
    END
  END rw0_wd_in[169]
  PIN rw0_wd_in[170]
    DIRECTION INPUT ;
    USE SIGNAL ;
    SHAPE ABUTMENT ;
    PORT
      LAYER M3 ;
      RECT 18.977 0.000 18.991 0.042 ;
    END
  END rw0_wd_in[170]
  PIN rw0_wd_in[171]
    DIRECTION INPUT ;
    USE SIGNAL ;
    SHAPE ABUTMENT ;
    PORT
      LAYER M3 ;
      RECT 19.425 0.000 19.439 0.042 ;
    END
  END rw0_wd_in[171]
  PIN rw0_wd_in[172]
    DIRECTION INPUT ;
    USE SIGNAL ;
    SHAPE ABUTMENT ;
    PORT
      LAYER M3 ;
      RECT 19.873 0.000 19.887 0.042 ;
    END
  END rw0_wd_in[172]
  PIN rw0_wd_in[173]
    DIRECTION INPUT ;
    USE SIGNAL ;
    SHAPE ABUTMENT ;
    PORT
      LAYER M3 ;
      RECT 20.321 0.000 20.335 0.042 ;
    END
  END rw0_wd_in[173]
  PIN rw0_wd_in[174]
    DIRECTION INPUT ;
    USE SIGNAL ;
    SHAPE ABUTMENT ;
    PORT
      LAYER M3 ;
      RECT 20.769 0.000 20.783 0.042 ;
    END
  END rw0_wd_in[174]
  PIN rw0_wd_in[175]
    DIRECTION INPUT ;
    USE SIGNAL ;
    SHAPE ABUTMENT ;
    PORT
      LAYER M3 ;
      RECT 21.217 0.000 21.231 0.042 ;
    END
  END rw0_wd_in[175]
  PIN rw0_wd_in[176]
    DIRECTION INPUT ;
    USE SIGNAL ;
    SHAPE ABUTMENT ;
    PORT
      LAYER M3 ;
      RECT 21.665 0.000 21.679 0.042 ;
    END
  END rw0_wd_in[176]
  PIN rw0_wd_in[177]
    DIRECTION INPUT ;
    USE SIGNAL ;
    SHAPE ABUTMENT ;
    PORT
      LAYER M3 ;
      RECT 22.113 0.000 22.127 0.042 ;
    END
  END rw0_wd_in[177]
  PIN rw0_wd_in[178]
    DIRECTION INPUT ;
    USE SIGNAL ;
    SHAPE ABUTMENT ;
    PORT
      LAYER M3 ;
      RECT 22.561 0.000 22.575 0.042 ;
    END
  END rw0_wd_in[178]
  PIN rw0_wd_in[179]
    DIRECTION INPUT ;
    USE SIGNAL ;
    SHAPE ABUTMENT ;
    PORT
      LAYER M3 ;
      RECT 23.009 0.000 23.023 0.042 ;
    END
  END rw0_wd_in[179]
  PIN rw0_wd_in[180]
    DIRECTION INPUT ;
    USE SIGNAL ;
    SHAPE ABUTMENT ;
    PORT
      LAYER M3 ;
      RECT 23.457 0.000 23.471 0.042 ;
    END
  END rw0_wd_in[180]
  PIN rw0_wd_in[181]
    DIRECTION INPUT ;
    USE SIGNAL ;
    SHAPE ABUTMENT ;
    PORT
      LAYER M3 ;
      RECT 23.905 0.000 23.919 0.042 ;
    END
  END rw0_wd_in[181]
  PIN rw0_wd_in[182]
    DIRECTION INPUT ;
    USE SIGNAL ;
    SHAPE ABUTMENT ;
    PORT
      LAYER M3 ;
      RECT 24.353 0.000 24.367 0.042 ;
    END
  END rw0_wd_in[182]
  PIN rw0_wd_in[183]
    DIRECTION INPUT ;
    USE SIGNAL ;
    SHAPE ABUTMENT ;
    PORT
      LAYER M3 ;
      RECT 24.801 0.000 24.815 0.042 ;
    END
  END rw0_wd_in[183]
  PIN rw0_wd_in[184]
    DIRECTION INPUT ;
    USE SIGNAL ;
    SHAPE ABUTMENT ;
    PORT
      LAYER M3 ;
      RECT 25.249 0.000 25.263 0.042 ;
    END
  END rw0_wd_in[184]
  PIN rw0_wd_in[185]
    DIRECTION INPUT ;
    USE SIGNAL ;
    SHAPE ABUTMENT ;
    PORT
      LAYER M3 ;
      RECT 25.697 0.000 25.711 0.042 ;
    END
  END rw0_wd_in[185]
  PIN rw0_wd_in[186]
    DIRECTION INPUT ;
    USE SIGNAL ;
    SHAPE ABUTMENT ;
    PORT
      LAYER M3 ;
      RECT 26.145 0.000 26.159 0.042 ;
    END
  END rw0_wd_in[186]
  PIN rw0_wd_in[187]
    DIRECTION INPUT ;
    USE SIGNAL ;
    SHAPE ABUTMENT ;
    PORT
      LAYER M3 ;
      RECT 26.593 0.000 26.607 0.042 ;
    END
  END rw0_wd_in[187]
  PIN rw0_wd_in[188]
    DIRECTION INPUT ;
    USE SIGNAL ;
    SHAPE ABUTMENT ;
    PORT
      LAYER M3 ;
      RECT 27.041 0.000 27.055 0.042 ;
    END
  END rw0_wd_in[188]
  PIN rw0_wd_in[189]
    DIRECTION INPUT ;
    USE SIGNAL ;
    SHAPE ABUTMENT ;
    PORT
      LAYER M3 ;
      RECT 27.489 0.000 27.503 0.042 ;
    END
  END rw0_wd_in[189]
  PIN rw0_wd_in[190]
    DIRECTION INPUT ;
    USE SIGNAL ;
    SHAPE ABUTMENT ;
    PORT
      LAYER M3 ;
      RECT 27.937 0.000 27.951 0.042 ;
    END
  END rw0_wd_in[190]
  PIN rw0_wd_in[191]
    DIRECTION INPUT ;
    USE SIGNAL ;
    SHAPE ABUTMENT ;
    PORT
      LAYER M3 ;
      RECT 28.385 0.000 28.399 0.042 ;
    END
  END rw0_wd_in[191]
  PIN rw0_wd_in[192]
    DIRECTION INPUT ;
    USE SIGNAL ;
    SHAPE ABUTMENT ;
    PORT
      LAYER M3 ;
      RECT 28.833 0.000 28.847 0.042 ;
    END
  END rw0_wd_in[192]
  PIN rw0_wd_in[193]
    DIRECTION INPUT ;
    USE SIGNAL ;
    SHAPE ABUTMENT ;
    PORT
      LAYER M3 ;
      RECT 29.281 0.000 29.295 0.042 ;
    END
  END rw0_wd_in[193]
  PIN rw0_wd_in[194]
    DIRECTION INPUT ;
    USE SIGNAL ;
    SHAPE ABUTMENT ;
    PORT
      LAYER M3 ;
      RECT 29.729 0.000 29.743 0.042 ;
    END
  END rw0_wd_in[194]
  PIN rw0_wd_in[195]
    DIRECTION INPUT ;
    USE SIGNAL ;
    SHAPE ABUTMENT ;
    PORT
      LAYER M3 ;
      RECT 30.177 0.000 30.191 0.042 ;
    END
  END rw0_wd_in[195]
  PIN rw0_wd_in[196]
    DIRECTION INPUT ;
    USE SIGNAL ;
    SHAPE ABUTMENT ;
    PORT
      LAYER M3 ;
      RECT 30.625 0.000 30.639 0.042 ;
    END
  END rw0_wd_in[196]
  PIN rw0_wd_in[197]
    DIRECTION INPUT ;
    USE SIGNAL ;
    SHAPE ABUTMENT ;
    PORT
      LAYER M3 ;
      RECT 31.073 0.000 31.087 0.042 ;
    END
  END rw0_wd_in[197]
  PIN rw0_wd_in[198]
    DIRECTION INPUT ;
    USE SIGNAL ;
    SHAPE ABUTMENT ;
    PORT
      LAYER M3 ;
      RECT 31.521 0.000 31.535 0.042 ;
    END
  END rw0_wd_in[198]
  PIN rw0_wd_in[199]
    DIRECTION INPUT ;
    USE SIGNAL ;
    SHAPE ABUTMENT ;
    PORT
      LAYER M3 ;
      RECT 31.969 0.000 31.983 0.042 ;
    END
  END rw0_wd_in[199]
  PIN rw0_wd_in[200]
    DIRECTION INPUT ;
    USE SIGNAL ;
    SHAPE ABUTMENT ;
    PORT
      LAYER M3 ;
      RECT 32.417 0.000 32.431 0.042 ;
    END
  END rw0_wd_in[200]
  PIN rw0_wd_in[201]
    DIRECTION INPUT ;
    USE SIGNAL ;
    SHAPE ABUTMENT ;
    PORT
      LAYER M3 ;
      RECT 32.865 0.000 32.879 0.042 ;
    END
  END rw0_wd_in[201]
  PIN rw0_wd_in[202]
    DIRECTION INPUT ;
    USE SIGNAL ;
    SHAPE ABUTMENT ;
    PORT
      LAYER M3 ;
      RECT 33.313 0.000 33.327 0.042 ;
    END
  END rw0_wd_in[202]
  PIN rw0_wd_in[203]
    DIRECTION INPUT ;
    USE SIGNAL ;
    SHAPE ABUTMENT ;
    PORT
      LAYER M3 ;
      RECT 33.761 0.000 33.775 0.042 ;
    END
  END rw0_wd_in[203]
  PIN rw0_wd_in[204]
    DIRECTION INPUT ;
    USE SIGNAL ;
    SHAPE ABUTMENT ;
    PORT
      LAYER M3 ;
      RECT 34.209 0.000 34.223 0.042 ;
    END
  END rw0_wd_in[204]
  PIN rw0_wd_in[205]
    DIRECTION INPUT ;
    USE SIGNAL ;
    SHAPE ABUTMENT ;
    PORT
      LAYER M3 ;
      RECT 34.657 0.000 34.671 0.042 ;
    END
  END rw0_wd_in[205]
  PIN rw0_wd_in[206]
    DIRECTION INPUT ;
    USE SIGNAL ;
    SHAPE ABUTMENT ;
    PORT
      LAYER M3 ;
      RECT 35.105 0.000 35.119 0.042 ;
    END
  END rw0_wd_in[206]
  PIN rw0_wd_in[207]
    DIRECTION INPUT ;
    USE SIGNAL ;
    SHAPE ABUTMENT ;
    PORT
      LAYER M3 ;
      RECT 35.553 0.000 35.567 0.042 ;
    END
  END rw0_wd_in[207]
  PIN rw0_wd_in[208]
    DIRECTION INPUT ;
    USE SIGNAL ;
    SHAPE ABUTMENT ;
    PORT
      LAYER M3 ;
      RECT 36.001 0.000 36.015 0.042 ;
    END
  END rw0_wd_in[208]
  PIN rw0_wd_in[209]
    DIRECTION INPUT ;
    USE SIGNAL ;
    SHAPE ABUTMENT ;
    PORT
      LAYER M3 ;
      RECT 36.449 0.000 36.463 0.042 ;
    END
  END rw0_wd_in[209]
  PIN rw0_wd_in[210]
    DIRECTION INPUT ;
    USE SIGNAL ;
    SHAPE ABUTMENT ;
    PORT
      LAYER M3 ;
      RECT 36.897 0.000 36.911 0.042 ;
    END
  END rw0_wd_in[210]
  PIN rw0_wd_in[211]
    DIRECTION INPUT ;
    USE SIGNAL ;
    SHAPE ABUTMENT ;
    PORT
      LAYER M3 ;
      RECT 37.345 0.000 37.359 0.042 ;
    END
  END rw0_wd_in[211]
  PIN rw0_wd_in[212]
    DIRECTION INPUT ;
    USE SIGNAL ;
    SHAPE ABUTMENT ;
    PORT
      LAYER M3 ;
      RECT 37.793 0.000 37.807 0.042 ;
    END
  END rw0_wd_in[212]
  PIN rw0_wd_in[213]
    DIRECTION INPUT ;
    USE SIGNAL ;
    SHAPE ABUTMENT ;
    PORT
      LAYER M3 ;
      RECT 38.241 0.000 38.255 0.042 ;
    END
  END rw0_wd_in[213]
  PIN rw0_wd_in[214]
    DIRECTION INPUT ;
    USE SIGNAL ;
    SHAPE ABUTMENT ;
    PORT
      LAYER M3 ;
      RECT 38.689 0.000 38.703 0.042 ;
    END
  END rw0_wd_in[214]
  PIN rw0_wd_in[215]
    DIRECTION INPUT ;
    USE SIGNAL ;
    SHAPE ABUTMENT ;
    PORT
      LAYER M3 ;
      RECT 39.137 0.000 39.151 0.042 ;
    END
  END rw0_wd_in[215]
  PIN rw0_wd_in[216]
    DIRECTION INPUT ;
    USE SIGNAL ;
    SHAPE ABUTMENT ;
    PORT
      LAYER M3 ;
      RECT 39.585 0.000 39.599 0.042 ;
    END
  END rw0_wd_in[216]
  PIN rw0_wd_in[217]
    DIRECTION INPUT ;
    USE SIGNAL ;
    SHAPE ABUTMENT ;
    PORT
      LAYER M3 ;
      RECT 40.033 0.000 40.047 0.042 ;
    END
  END rw0_wd_in[217]
  PIN rw0_wd_in[218]
    DIRECTION INPUT ;
    USE SIGNAL ;
    SHAPE ABUTMENT ;
    PORT
      LAYER M3 ;
      RECT 40.481 0.000 40.495 0.042 ;
    END
  END rw0_wd_in[218]
  PIN rw0_wd_in[219]
    DIRECTION INPUT ;
    USE SIGNAL ;
    SHAPE ABUTMENT ;
    PORT
      LAYER M3 ;
      RECT 40.929 0.000 40.943 0.042 ;
    END
  END rw0_wd_in[219]
  PIN rw0_wd_in[220]
    DIRECTION INPUT ;
    USE SIGNAL ;
    SHAPE ABUTMENT ;
    PORT
      LAYER M3 ;
      RECT 41.377 0.000 41.391 0.042 ;
    END
  END rw0_wd_in[220]
  PIN rw0_wd_in[221]
    DIRECTION INPUT ;
    USE SIGNAL ;
    SHAPE ABUTMENT ;
    PORT
      LAYER M3 ;
      RECT 41.825 0.000 41.839 0.042 ;
    END
  END rw0_wd_in[221]
  PIN rw0_wd_in[222]
    DIRECTION INPUT ;
    USE SIGNAL ;
    SHAPE ABUTMENT ;
    PORT
      LAYER M3 ;
      RECT 42.273 0.000 42.287 0.042 ;
    END
  END rw0_wd_in[222]
  PIN rw0_wd_in[223]
    DIRECTION INPUT ;
    USE SIGNAL ;
    SHAPE ABUTMENT ;
    PORT
      LAYER M3 ;
      RECT 42.721 0.000 42.735 0.042 ;
    END
  END rw0_wd_in[223]
  PIN rw0_wd_in[224]
    DIRECTION INPUT ;
    USE SIGNAL ;
    SHAPE ABUTMENT ;
    PORT
      LAYER M3 ;
      RECT 43.169 0.000 43.183 0.042 ;
    END
  END rw0_wd_in[224]
  PIN rw0_wd_in[225]
    DIRECTION INPUT ;
    USE SIGNAL ;
    SHAPE ABUTMENT ;
    PORT
      LAYER M3 ;
      RECT 43.617 0.000 43.631 0.042 ;
    END
  END rw0_wd_in[225]
  PIN rw0_wd_in[226]
    DIRECTION INPUT ;
    USE SIGNAL ;
    SHAPE ABUTMENT ;
    PORT
      LAYER M3 ;
      RECT 44.065 0.000 44.079 0.042 ;
    END
  END rw0_wd_in[226]
  PIN rw0_wd_in[227]
    DIRECTION INPUT ;
    USE SIGNAL ;
    SHAPE ABUTMENT ;
    PORT
      LAYER M3 ;
      RECT 44.513 0.000 44.527 0.042 ;
    END
  END rw0_wd_in[227]
  PIN rw0_wd_in[228]
    DIRECTION INPUT ;
    USE SIGNAL ;
    SHAPE ABUTMENT ;
    PORT
      LAYER M3 ;
      RECT 44.961 0.000 44.975 0.042 ;
    END
  END rw0_wd_in[228]
  PIN rw0_wd_in[229]
    DIRECTION INPUT ;
    USE SIGNAL ;
    SHAPE ABUTMENT ;
    PORT
      LAYER M3 ;
      RECT 45.409 0.000 45.423 0.042 ;
    END
  END rw0_wd_in[229]
  PIN rw0_wd_in[230]
    DIRECTION INPUT ;
    USE SIGNAL ;
    SHAPE ABUTMENT ;
    PORT
      LAYER M3 ;
      RECT 45.857 0.000 45.871 0.042 ;
    END
  END rw0_wd_in[230]
  PIN rw0_wd_in[231]
    DIRECTION INPUT ;
    USE SIGNAL ;
    SHAPE ABUTMENT ;
    PORT
      LAYER M3 ;
      RECT 46.305 0.000 46.319 0.042 ;
    END
  END rw0_wd_in[231]
  PIN rw0_wd_in[232]
    DIRECTION INPUT ;
    USE SIGNAL ;
    SHAPE ABUTMENT ;
    PORT
      LAYER M3 ;
      RECT 46.753 0.000 46.767 0.042 ;
    END
  END rw0_wd_in[232]
  PIN rw0_wd_in[233]
    DIRECTION INPUT ;
    USE SIGNAL ;
    SHAPE ABUTMENT ;
    PORT
      LAYER M3 ;
      RECT 47.201 0.000 47.215 0.042 ;
    END
  END rw0_wd_in[233]
  PIN rw0_wd_in[234]
    DIRECTION INPUT ;
    USE SIGNAL ;
    SHAPE ABUTMENT ;
    PORT
      LAYER M3 ;
      RECT 47.649 0.000 47.663 0.042 ;
    END
  END rw0_wd_in[234]
  PIN rw0_wd_in[235]
    DIRECTION INPUT ;
    USE SIGNAL ;
    SHAPE ABUTMENT ;
    PORT
      LAYER M3 ;
      RECT 48.097 0.000 48.111 0.042 ;
    END
  END rw0_wd_in[235]
  PIN rw0_wd_in[236]
    DIRECTION INPUT ;
    USE SIGNAL ;
    SHAPE ABUTMENT ;
    PORT
      LAYER M3 ;
      RECT 48.545 0.000 48.559 0.042 ;
    END
  END rw0_wd_in[236]
  PIN rw0_wd_in[237]
    DIRECTION INPUT ;
    USE SIGNAL ;
    SHAPE ABUTMENT ;
    PORT
      LAYER M3 ;
      RECT 48.993 0.000 49.007 0.042 ;
    END
  END rw0_wd_in[237]
  PIN rw0_wd_in[238]
    DIRECTION INPUT ;
    USE SIGNAL ;
    SHAPE ABUTMENT ;
    PORT
      LAYER M3 ;
      RECT 49.441 0.000 49.455 0.042 ;
    END
  END rw0_wd_in[238]
  PIN rw0_wd_in[239]
    DIRECTION INPUT ;
    USE SIGNAL ;
    SHAPE ABUTMENT ;
    PORT
      LAYER M3 ;
      RECT 49.889 0.000 49.903 0.042 ;
    END
  END rw0_wd_in[239]
  PIN rw0_wd_in[240]
    DIRECTION INPUT ;
    USE SIGNAL ;
    SHAPE ABUTMENT ;
    PORT
      LAYER M3 ;
      RECT 50.337 0.000 50.351 0.042 ;
    END
  END rw0_wd_in[240]
  PIN rw0_wd_in[241]
    DIRECTION INPUT ;
    USE SIGNAL ;
    SHAPE ABUTMENT ;
    PORT
      LAYER M3 ;
      RECT 50.785 0.000 50.799 0.042 ;
    END
  END rw0_wd_in[241]
  PIN rw0_wd_in[242]
    DIRECTION INPUT ;
    USE SIGNAL ;
    SHAPE ABUTMENT ;
    PORT
      LAYER M3 ;
      RECT 51.233 0.000 51.247 0.042 ;
    END
  END rw0_wd_in[242]
  PIN rw0_wd_in[243]
    DIRECTION INPUT ;
    USE SIGNAL ;
    SHAPE ABUTMENT ;
    PORT
      LAYER M3 ;
      RECT 51.681 0.000 51.695 0.042 ;
    END
  END rw0_wd_in[243]
  PIN rw0_wd_in[244]
    DIRECTION INPUT ;
    USE SIGNAL ;
    SHAPE ABUTMENT ;
    PORT
      LAYER M3 ;
      RECT 52.129 0.000 52.143 0.042 ;
    END
  END rw0_wd_in[244]
  PIN rw0_wd_in[245]
    DIRECTION INPUT ;
    USE SIGNAL ;
    SHAPE ABUTMENT ;
    PORT
      LAYER M3 ;
      RECT 52.577 0.000 52.591 0.042 ;
    END
  END rw0_wd_in[245]
  PIN rw0_wd_in[246]
    DIRECTION INPUT ;
    USE SIGNAL ;
    SHAPE ABUTMENT ;
    PORT
      LAYER M3 ;
      RECT 53.025 0.000 53.039 0.042 ;
    END
  END rw0_wd_in[246]
  PIN rw0_wd_in[247]
    DIRECTION INPUT ;
    USE SIGNAL ;
    SHAPE ABUTMENT ;
    PORT
      LAYER M3 ;
      RECT 53.473 0.000 53.487 0.042 ;
    END
  END rw0_wd_in[247]
  PIN rw0_wd_in[248]
    DIRECTION INPUT ;
    USE SIGNAL ;
    SHAPE ABUTMENT ;
    PORT
      LAYER M3 ;
      RECT 53.921 0.000 53.935 0.042 ;
    END
  END rw0_wd_in[248]
  PIN rw0_wd_in[249]
    DIRECTION INPUT ;
    USE SIGNAL ;
    SHAPE ABUTMENT ;
    PORT
      LAYER M3 ;
      RECT 54.369 0.000 54.383 0.042 ;
    END
  END rw0_wd_in[249]
  PIN rw0_wd_in[250]
    DIRECTION INPUT ;
    USE SIGNAL ;
    SHAPE ABUTMENT ;
    PORT
      LAYER M3 ;
      RECT 54.817 0.000 54.831 0.042 ;
    END
  END rw0_wd_in[250]
  PIN rw0_wd_in[251]
    DIRECTION INPUT ;
    USE SIGNAL ;
    SHAPE ABUTMENT ;
    PORT
      LAYER M3 ;
      RECT 55.265 0.000 55.279 0.042 ;
    END
  END rw0_wd_in[251]
  PIN rw0_wd_in[252]
    DIRECTION INPUT ;
    USE SIGNAL ;
    SHAPE ABUTMENT ;
    PORT
      LAYER M3 ;
      RECT 55.713 0.000 55.727 0.042 ;
    END
  END rw0_wd_in[252]
  PIN rw0_wd_in[253]
    DIRECTION INPUT ;
    USE SIGNAL ;
    SHAPE ABUTMENT ;
    PORT
      LAYER M3 ;
      RECT 56.161 0.000 56.175 0.042 ;
    END
  END rw0_wd_in[253]
  PIN rw0_wd_in[254]
    DIRECTION INPUT ;
    USE SIGNAL ;
    SHAPE ABUTMENT ;
    PORT
      LAYER M3 ;
      RECT 56.609 0.000 56.623 0.042 ;
    END
  END rw0_wd_in[254]
  PIN rw0_wd_in[255]
    DIRECTION INPUT ;
    USE SIGNAL ;
    SHAPE ABUTMENT ;
    PORT
      LAYER M3 ;
      RECT 57.057 0.000 57.071 0.042 ;
    END
  END rw0_wd_in[255]
  PIN rw0_rd_out[0]
    DIRECTION OUTPUT ;
    USE SIGNAL ;
    SHAPE ABUTMENT ;
    PORT
      LAYER M3 ;
      RECT 57.505 0.000 57.519 0.042 ;
    END
  END rw0_rd_out[0]
  PIN rw0_rd_out[1]
    DIRECTION OUTPUT ;
    USE SIGNAL ;
    SHAPE ABUTMENT ;
    PORT
      LAYER M3 ;
      RECT 57.953 0.000 57.967 0.042 ;
    END
  END rw0_rd_out[1]
  PIN rw0_rd_out[2]
    DIRECTION OUTPUT ;
    USE SIGNAL ;
    SHAPE ABUTMENT ;
    PORT
      LAYER M3 ;
      RECT 58.401 0.000 58.415 0.042 ;
    END
  END rw0_rd_out[2]
  PIN rw0_rd_out[3]
    DIRECTION OUTPUT ;
    USE SIGNAL ;
    SHAPE ABUTMENT ;
    PORT
      LAYER M3 ;
      RECT 58.849 0.000 58.863 0.042 ;
    END
  END rw0_rd_out[3]
  PIN rw0_rd_out[4]
    DIRECTION OUTPUT ;
    USE SIGNAL ;
    SHAPE ABUTMENT ;
    PORT
      LAYER M3 ;
      RECT 59.297 0.000 59.311 0.042 ;
    END
  END rw0_rd_out[4]
  PIN rw0_rd_out[5]
    DIRECTION OUTPUT ;
    USE SIGNAL ;
    SHAPE ABUTMENT ;
    PORT
      LAYER M3 ;
      RECT 59.745 0.000 59.759 0.042 ;
    END
  END rw0_rd_out[5]
  PIN rw0_rd_out[6]
    DIRECTION OUTPUT ;
    USE SIGNAL ;
    SHAPE ABUTMENT ;
    PORT
      LAYER M3 ;
      RECT 60.193 0.000 60.207 0.042 ;
    END
  END rw0_rd_out[6]
  PIN rw0_rd_out[7]
    DIRECTION OUTPUT ;
    USE SIGNAL ;
    SHAPE ABUTMENT ;
    PORT
      LAYER M3 ;
      RECT 60.641 0.000 60.655 0.042 ;
    END
  END rw0_rd_out[7]
  PIN rw0_rd_out[8]
    DIRECTION OUTPUT ;
    USE SIGNAL ;
    SHAPE ABUTMENT ;
    PORT
      LAYER M3 ;
      RECT 61.089 0.000 61.103 0.042 ;
    END
  END rw0_rd_out[8]
  PIN rw0_rd_out[9]
    DIRECTION OUTPUT ;
    USE SIGNAL ;
    SHAPE ABUTMENT ;
    PORT
      LAYER M3 ;
      RECT 61.537 0.000 61.551 0.042 ;
    END
  END rw0_rd_out[9]
  PIN rw0_rd_out[10]
    DIRECTION OUTPUT ;
    USE SIGNAL ;
    SHAPE ABUTMENT ;
    PORT
      LAYER M3 ;
      RECT 61.985 0.000 61.999 0.042 ;
    END
  END rw0_rd_out[10]
  PIN rw0_rd_out[11]
    DIRECTION OUTPUT ;
    USE SIGNAL ;
    SHAPE ABUTMENT ;
    PORT
      LAYER M3 ;
      RECT 62.433 0.000 62.447 0.042 ;
    END
  END rw0_rd_out[11]
  PIN rw0_rd_out[12]
    DIRECTION OUTPUT ;
    USE SIGNAL ;
    SHAPE ABUTMENT ;
    PORT
      LAYER M3 ;
      RECT 62.881 0.000 62.895 0.042 ;
    END
  END rw0_rd_out[12]
  PIN rw0_rd_out[13]
    DIRECTION OUTPUT ;
    USE SIGNAL ;
    SHAPE ABUTMENT ;
    PORT
      LAYER M3 ;
      RECT 63.329 0.000 63.343 0.042 ;
    END
  END rw0_rd_out[13]
  PIN rw0_rd_out[14]
    DIRECTION OUTPUT ;
    USE SIGNAL ;
    SHAPE ABUTMENT ;
    PORT
      LAYER M3 ;
      RECT 63.777 0.000 63.791 0.042 ;
    END
  END rw0_rd_out[14]
  PIN rw0_rd_out[15]
    DIRECTION OUTPUT ;
    USE SIGNAL ;
    SHAPE ABUTMENT ;
    PORT
      LAYER M3 ;
      RECT 64.225 0.000 64.239 0.042 ;
    END
  END rw0_rd_out[15]
  PIN rw0_rd_out[16]
    DIRECTION OUTPUT ;
    USE SIGNAL ;
    SHAPE ABUTMENT ;
    PORT
      LAYER M3 ;
      RECT 64.673 0.000 64.687 0.042 ;
    END
  END rw0_rd_out[16]
  PIN rw0_rd_out[17]
    DIRECTION OUTPUT ;
    USE SIGNAL ;
    SHAPE ABUTMENT ;
    PORT
      LAYER M3 ;
      RECT 65.121 0.000 65.135 0.042 ;
    END
  END rw0_rd_out[17]
  PIN rw0_rd_out[18]
    DIRECTION OUTPUT ;
    USE SIGNAL ;
    SHAPE ABUTMENT ;
    PORT
      LAYER M3 ;
      RECT 65.569 0.000 65.583 0.042 ;
    END
  END rw0_rd_out[18]
  PIN rw0_rd_out[19]
    DIRECTION OUTPUT ;
    USE SIGNAL ;
    SHAPE ABUTMENT ;
    PORT
      LAYER M3 ;
      RECT 66.017 0.000 66.031 0.042 ;
    END
  END rw0_rd_out[19]
  PIN rw0_rd_out[20]
    DIRECTION OUTPUT ;
    USE SIGNAL ;
    SHAPE ABUTMENT ;
    PORT
      LAYER M3 ;
      RECT 66.465 0.000 66.479 0.042 ;
    END
  END rw0_rd_out[20]
  PIN rw0_rd_out[21]
    DIRECTION OUTPUT ;
    USE SIGNAL ;
    SHAPE ABUTMENT ;
    PORT
      LAYER M3 ;
      RECT 66.913 0.000 66.927 0.042 ;
    END
  END rw0_rd_out[21]
  PIN rw0_rd_out[22]
    DIRECTION OUTPUT ;
    USE SIGNAL ;
    SHAPE ABUTMENT ;
    PORT
      LAYER M3 ;
      RECT 67.361 0.000 67.375 0.042 ;
    END
  END rw0_rd_out[22]
  PIN rw0_rd_out[23]
    DIRECTION OUTPUT ;
    USE SIGNAL ;
    SHAPE ABUTMENT ;
    PORT
      LAYER M3 ;
      RECT 67.809 0.000 67.823 0.042 ;
    END
  END rw0_rd_out[23]
  PIN rw0_rd_out[24]
    DIRECTION OUTPUT ;
    USE SIGNAL ;
    SHAPE ABUTMENT ;
    PORT
      LAYER M3 ;
      RECT 68.257 0.000 68.271 0.042 ;
    END
  END rw0_rd_out[24]
  PIN rw0_rd_out[25]
    DIRECTION OUTPUT ;
    USE SIGNAL ;
    SHAPE ABUTMENT ;
    PORT
      LAYER M3 ;
      RECT 68.705 0.000 68.719 0.042 ;
    END
  END rw0_rd_out[25]
  PIN rw0_rd_out[26]
    DIRECTION OUTPUT ;
    USE SIGNAL ;
    SHAPE ABUTMENT ;
    PORT
      LAYER M3 ;
      RECT 69.153 0.000 69.167 0.042 ;
    END
  END rw0_rd_out[26]
  PIN rw0_rd_out[27]
    DIRECTION OUTPUT ;
    USE SIGNAL ;
    SHAPE ABUTMENT ;
    PORT
      LAYER M3 ;
      RECT 69.601 0.000 69.615 0.042 ;
    END
  END rw0_rd_out[27]
  PIN rw0_rd_out[28]
    DIRECTION OUTPUT ;
    USE SIGNAL ;
    SHAPE ABUTMENT ;
    PORT
      LAYER M3 ;
      RECT 70.049 0.000 70.063 0.042 ;
    END
  END rw0_rd_out[28]
  PIN rw0_rd_out[29]
    DIRECTION OUTPUT ;
    USE SIGNAL ;
    SHAPE ABUTMENT ;
    PORT
      LAYER M3 ;
      RECT 70.497 0.000 70.511 0.042 ;
    END
  END rw0_rd_out[29]
  PIN rw0_rd_out[30]
    DIRECTION OUTPUT ;
    USE SIGNAL ;
    SHAPE ABUTMENT ;
    PORT
      LAYER M3 ;
      RECT 70.945 0.000 70.959 0.042 ;
    END
  END rw0_rd_out[30]
  PIN rw0_rd_out[31]
    DIRECTION OUTPUT ;
    USE SIGNAL ;
    SHAPE ABUTMENT ;
    PORT
      LAYER M3 ;
      RECT 71.393 0.000 71.407 0.042 ;
    END
  END rw0_rd_out[31]
  PIN rw0_rd_out[32]
    DIRECTION OUTPUT ;
    USE SIGNAL ;
    SHAPE ABUTMENT ;
    PORT
      LAYER M3 ;
      RECT 71.841 0.000 71.855 0.042 ;
    END
  END rw0_rd_out[32]
  PIN rw0_rd_out[33]
    DIRECTION OUTPUT ;
    USE SIGNAL ;
    SHAPE ABUTMENT ;
    PORT
      LAYER M3 ;
      RECT 72.289 0.000 72.303 0.042 ;
    END
  END rw0_rd_out[33]
  PIN rw0_rd_out[34]
    DIRECTION OUTPUT ;
    USE SIGNAL ;
    SHAPE ABUTMENT ;
    PORT
      LAYER M3 ;
      RECT 72.737 0.000 72.751 0.042 ;
    END
  END rw0_rd_out[34]
  PIN rw0_rd_out[35]
    DIRECTION OUTPUT ;
    USE SIGNAL ;
    SHAPE ABUTMENT ;
    PORT
      LAYER M3 ;
      RECT 73.185 0.000 73.199 0.042 ;
    END
  END rw0_rd_out[35]
  PIN rw0_rd_out[36]
    DIRECTION OUTPUT ;
    USE SIGNAL ;
    SHAPE ABUTMENT ;
    PORT
      LAYER M3 ;
      RECT 73.633 0.000 73.647 0.042 ;
    END
  END rw0_rd_out[36]
  PIN rw0_rd_out[37]
    DIRECTION OUTPUT ;
    USE SIGNAL ;
    SHAPE ABUTMENT ;
    PORT
      LAYER M3 ;
      RECT 74.081 0.000 74.095 0.042 ;
    END
  END rw0_rd_out[37]
  PIN rw0_rd_out[38]
    DIRECTION OUTPUT ;
    USE SIGNAL ;
    SHAPE ABUTMENT ;
    PORT
      LAYER M3 ;
      RECT 74.529 0.000 74.543 0.042 ;
    END
  END rw0_rd_out[38]
  PIN rw0_rd_out[39]
    DIRECTION OUTPUT ;
    USE SIGNAL ;
    SHAPE ABUTMENT ;
    PORT
      LAYER M3 ;
      RECT 74.977 0.000 74.991 0.042 ;
    END
  END rw0_rd_out[39]
  PIN rw0_rd_out[40]
    DIRECTION OUTPUT ;
    USE SIGNAL ;
    SHAPE ABUTMENT ;
    PORT
      LAYER M3 ;
      RECT 75.425 0.000 75.439 0.042 ;
    END
  END rw0_rd_out[40]
  PIN rw0_rd_out[41]
    DIRECTION OUTPUT ;
    USE SIGNAL ;
    SHAPE ABUTMENT ;
    PORT
      LAYER M3 ;
      RECT 75.873 0.000 75.887 0.042 ;
    END
  END rw0_rd_out[41]
  PIN rw0_rd_out[42]
    DIRECTION OUTPUT ;
    USE SIGNAL ;
    SHAPE ABUTMENT ;
    PORT
      LAYER M3 ;
      RECT 76.321 0.000 76.335 0.042 ;
    END
  END rw0_rd_out[42]
  PIN rw0_rd_out[43]
    DIRECTION OUTPUT ;
    USE SIGNAL ;
    SHAPE ABUTMENT ;
    PORT
      LAYER M3 ;
      RECT 76.769 0.000 76.783 0.042 ;
    END
  END rw0_rd_out[43]
  PIN rw0_rd_out[44]
    DIRECTION OUTPUT ;
    USE SIGNAL ;
    SHAPE ABUTMENT ;
    PORT
      LAYER M3 ;
      RECT 77.217 0.000 77.231 0.042 ;
    END
  END rw0_rd_out[44]
  PIN rw0_rd_out[45]
    DIRECTION OUTPUT ;
    USE SIGNAL ;
    SHAPE ABUTMENT ;
    PORT
      LAYER M3 ;
      RECT 77.665 0.000 77.679 0.042 ;
    END
  END rw0_rd_out[45]
  PIN rw0_rd_out[46]
    DIRECTION OUTPUT ;
    USE SIGNAL ;
    SHAPE ABUTMENT ;
    PORT
      LAYER M3 ;
      RECT 78.113 0.000 78.127 0.042 ;
    END
  END rw0_rd_out[46]
  PIN rw0_rd_out[47]
    DIRECTION OUTPUT ;
    USE SIGNAL ;
    SHAPE ABUTMENT ;
    PORT
      LAYER M3 ;
      RECT 78.561 0.000 78.575 0.042 ;
    END
  END rw0_rd_out[47]
  PIN rw0_rd_out[48]
    DIRECTION OUTPUT ;
    USE SIGNAL ;
    SHAPE ABUTMENT ;
    PORT
      LAYER M3 ;
      RECT 79.009 0.000 79.023 0.042 ;
    END
  END rw0_rd_out[48]
  PIN rw0_rd_out[49]
    DIRECTION OUTPUT ;
    USE SIGNAL ;
    SHAPE ABUTMENT ;
    PORT
      LAYER M3 ;
      RECT 79.457 0.000 79.471 0.042 ;
    END
  END rw0_rd_out[49]
  PIN rw0_rd_out[50]
    DIRECTION OUTPUT ;
    USE SIGNAL ;
    SHAPE ABUTMENT ;
    PORT
      LAYER M3 ;
      RECT 79.905 0.000 79.919 0.042 ;
    END
  END rw0_rd_out[50]
  PIN rw0_rd_out[51]
    DIRECTION OUTPUT ;
    USE SIGNAL ;
    SHAPE ABUTMENT ;
    PORT
      LAYER M3 ;
      RECT 80.353 0.000 80.367 0.042 ;
    END
  END rw0_rd_out[51]
  PIN rw0_rd_out[52]
    DIRECTION OUTPUT ;
    USE SIGNAL ;
    SHAPE ABUTMENT ;
    PORT
      LAYER M3 ;
      RECT 80.801 0.000 80.815 0.042 ;
    END
  END rw0_rd_out[52]
  PIN rw0_rd_out[53]
    DIRECTION OUTPUT ;
    USE SIGNAL ;
    SHAPE ABUTMENT ;
    PORT
      LAYER M3 ;
      RECT 81.249 0.000 81.263 0.042 ;
    END
  END rw0_rd_out[53]
  PIN rw0_rd_out[54]
    DIRECTION OUTPUT ;
    USE SIGNAL ;
    SHAPE ABUTMENT ;
    PORT
      LAYER M3 ;
      RECT 81.697 0.000 81.711 0.042 ;
    END
  END rw0_rd_out[54]
  PIN rw0_rd_out[55]
    DIRECTION OUTPUT ;
    USE SIGNAL ;
    SHAPE ABUTMENT ;
    PORT
      LAYER M3 ;
      RECT 82.145 0.000 82.159 0.042 ;
    END
  END rw0_rd_out[55]
  PIN rw0_rd_out[56]
    DIRECTION OUTPUT ;
    USE SIGNAL ;
    SHAPE ABUTMENT ;
    PORT
      LAYER M3 ;
      RECT 82.593 0.000 82.607 0.042 ;
    END
  END rw0_rd_out[56]
  PIN rw0_rd_out[57]
    DIRECTION OUTPUT ;
    USE SIGNAL ;
    SHAPE ABUTMENT ;
    PORT
      LAYER M3 ;
      RECT 83.041 0.000 83.055 0.042 ;
    END
  END rw0_rd_out[57]
  PIN rw0_rd_out[58]
    DIRECTION OUTPUT ;
    USE SIGNAL ;
    SHAPE ABUTMENT ;
    PORT
      LAYER M3 ;
      RECT 83.489 0.000 83.503 0.042 ;
    END
  END rw0_rd_out[58]
  PIN rw0_rd_out[59]
    DIRECTION OUTPUT ;
    USE SIGNAL ;
    SHAPE ABUTMENT ;
    PORT
      LAYER M3 ;
      RECT 83.937 0.000 83.951 0.042 ;
    END
  END rw0_rd_out[59]
  PIN rw0_rd_out[60]
    DIRECTION OUTPUT ;
    USE SIGNAL ;
    SHAPE ABUTMENT ;
    PORT
      LAYER M3 ;
      RECT 84.385 0.000 84.399 0.042 ;
    END
  END rw0_rd_out[60]
  PIN rw0_rd_out[61]
    DIRECTION OUTPUT ;
    USE SIGNAL ;
    SHAPE ABUTMENT ;
    PORT
      LAYER M3 ;
      RECT 84.833 0.000 84.847 0.042 ;
    END
  END rw0_rd_out[61]
  PIN rw0_rd_out[62]
    DIRECTION OUTPUT ;
    USE SIGNAL ;
    SHAPE ABUTMENT ;
    PORT
      LAYER M3 ;
      RECT 85.281 0.000 85.295 0.042 ;
    END
  END rw0_rd_out[62]
  PIN rw0_rd_out[63]
    DIRECTION OUTPUT ;
    USE SIGNAL ;
    SHAPE ABUTMENT ;
    PORT
      LAYER M3 ;
      RECT 85.729 0.000 85.743 0.042 ;
    END
  END rw0_rd_out[63]
  PIN rw0_rd_out[64]
    DIRECTION OUTPUT ;
    USE SIGNAL ;
    SHAPE ABUTMENT ;
    PORT
      LAYER M3 ;
      RECT 86.177 0.000 86.191 0.042 ;
    END
  END rw0_rd_out[64]
  PIN rw0_rd_out[65]
    DIRECTION OUTPUT ;
    USE SIGNAL ;
    SHAPE ABUTMENT ;
    PORT
      LAYER M3 ;
      RECT 86.625 0.000 86.639 0.042 ;
    END
  END rw0_rd_out[65]
  PIN rw0_rd_out[66]
    DIRECTION OUTPUT ;
    USE SIGNAL ;
    SHAPE ABUTMENT ;
    PORT
      LAYER M3 ;
      RECT 87.073 0.000 87.087 0.042 ;
    END
  END rw0_rd_out[66]
  PIN rw0_rd_out[67]
    DIRECTION OUTPUT ;
    USE SIGNAL ;
    SHAPE ABUTMENT ;
    PORT
      LAYER M3 ;
      RECT 87.521 0.000 87.535 0.042 ;
    END
  END rw0_rd_out[67]
  PIN rw0_rd_out[68]
    DIRECTION OUTPUT ;
    USE SIGNAL ;
    SHAPE ABUTMENT ;
    PORT
      LAYER M3 ;
      RECT 87.969 0.000 87.983 0.042 ;
    END
  END rw0_rd_out[68]
  PIN rw0_rd_out[69]
    DIRECTION OUTPUT ;
    USE SIGNAL ;
    SHAPE ABUTMENT ;
    PORT
      LAYER M3 ;
      RECT 88.417 0.000 88.431 0.042 ;
    END
  END rw0_rd_out[69]
  PIN rw0_rd_out[70]
    DIRECTION OUTPUT ;
    USE SIGNAL ;
    SHAPE ABUTMENT ;
    PORT
      LAYER M3 ;
      RECT 88.865 0.000 88.879 0.042 ;
    END
  END rw0_rd_out[70]
  PIN rw0_rd_out[71]
    DIRECTION OUTPUT ;
    USE SIGNAL ;
    SHAPE ABUTMENT ;
    PORT
      LAYER M3 ;
      RECT 89.313 0.000 89.327 0.042 ;
    END
  END rw0_rd_out[71]
  PIN rw0_rd_out[72]
    DIRECTION OUTPUT ;
    USE SIGNAL ;
    SHAPE ABUTMENT ;
    PORT
      LAYER M3 ;
      RECT 89.761 0.000 89.775 0.042 ;
    END
  END rw0_rd_out[72]
  PIN rw0_rd_out[73]
    DIRECTION OUTPUT ;
    USE SIGNAL ;
    SHAPE ABUTMENT ;
    PORT
      LAYER M3 ;
      RECT 90.209 0.000 90.223 0.042 ;
    END
  END rw0_rd_out[73]
  PIN rw0_rd_out[74]
    DIRECTION OUTPUT ;
    USE SIGNAL ;
    SHAPE ABUTMENT ;
    PORT
      LAYER M3 ;
      RECT 90.657 0.000 90.671 0.042 ;
    END
  END rw0_rd_out[74]
  PIN rw0_rd_out[75]
    DIRECTION OUTPUT ;
    USE SIGNAL ;
    SHAPE ABUTMENT ;
    PORT
      LAYER M3 ;
      RECT 91.105 0.000 91.119 0.042 ;
    END
  END rw0_rd_out[75]
  PIN rw0_rd_out[76]
    DIRECTION OUTPUT ;
    USE SIGNAL ;
    SHAPE ABUTMENT ;
    PORT
      LAYER M3 ;
      RECT 91.553 0.000 91.567 0.042 ;
    END
  END rw0_rd_out[76]
  PIN rw0_rd_out[77]
    DIRECTION OUTPUT ;
    USE SIGNAL ;
    SHAPE ABUTMENT ;
    PORT
      LAYER M3 ;
      RECT 92.001 0.000 92.015 0.042 ;
    END
  END rw0_rd_out[77]
  PIN rw0_rd_out[78]
    DIRECTION OUTPUT ;
    USE SIGNAL ;
    SHAPE ABUTMENT ;
    PORT
      LAYER M3 ;
      RECT 92.449 0.000 92.463 0.042 ;
    END
  END rw0_rd_out[78]
  PIN rw0_rd_out[79]
    DIRECTION OUTPUT ;
    USE SIGNAL ;
    SHAPE ABUTMENT ;
    PORT
      LAYER M3 ;
      RECT 92.897 0.000 92.911 0.042 ;
    END
  END rw0_rd_out[79]
  PIN rw0_rd_out[80]
    DIRECTION OUTPUT ;
    USE SIGNAL ;
    SHAPE ABUTMENT ;
    PORT
      LAYER M3 ;
      RECT 93.345 0.000 93.359 0.042 ;
    END
  END rw0_rd_out[80]
  PIN rw0_rd_out[81]
    DIRECTION OUTPUT ;
    USE SIGNAL ;
    SHAPE ABUTMENT ;
    PORT
      LAYER M3 ;
      RECT 93.793 0.000 93.807 0.042 ;
    END
  END rw0_rd_out[81]
  PIN rw0_rd_out[82]
    DIRECTION OUTPUT ;
    USE SIGNAL ;
    SHAPE ABUTMENT ;
    PORT
      LAYER M3 ;
      RECT 94.241 0.000 94.255 0.042 ;
    END
  END rw0_rd_out[82]
  PIN rw0_rd_out[83]
    DIRECTION OUTPUT ;
    USE SIGNAL ;
    SHAPE ABUTMENT ;
    PORT
      LAYER M3 ;
      RECT 94.689 0.000 94.703 0.042 ;
    END
  END rw0_rd_out[83]
  PIN rw0_rd_out[84]
    DIRECTION OUTPUT ;
    USE SIGNAL ;
    SHAPE ABUTMENT ;
    PORT
      LAYER M3 ;
      RECT 95.137 0.000 95.151 0.042 ;
    END
  END rw0_rd_out[84]
  PIN rw0_rd_out[85]
    DIRECTION OUTPUT ;
    USE SIGNAL ;
    SHAPE ABUTMENT ;
    PORT
      LAYER M3 ;
      RECT 95.585 0.000 95.599 0.042 ;
    END
  END rw0_rd_out[85]
  PIN rw0_rd_out[86]
    DIRECTION OUTPUT ;
    USE SIGNAL ;
    SHAPE ABUTMENT ;
    PORT
      LAYER M3 ;
      RECT 96.033 0.000 96.047 0.042 ;
    END
  END rw0_rd_out[86]
  PIN rw0_rd_out[87]
    DIRECTION OUTPUT ;
    USE SIGNAL ;
    SHAPE ABUTMENT ;
    PORT
      LAYER M3 ;
      RECT 96.481 0.000 96.495 0.042 ;
    END
  END rw0_rd_out[87]
  PIN rw0_rd_out[88]
    DIRECTION OUTPUT ;
    USE SIGNAL ;
    SHAPE ABUTMENT ;
    PORT
      LAYER M3 ;
      RECT 96.929 0.000 96.943 0.042 ;
    END
  END rw0_rd_out[88]
  PIN rw0_rd_out[89]
    DIRECTION OUTPUT ;
    USE SIGNAL ;
    SHAPE ABUTMENT ;
    PORT
      LAYER M3 ;
      RECT 97.377 0.000 97.391 0.042 ;
    END
  END rw0_rd_out[89]
  PIN rw0_rd_out[90]
    DIRECTION OUTPUT ;
    USE SIGNAL ;
    SHAPE ABUTMENT ;
    PORT
      LAYER M3 ;
      RECT 97.825 0.000 97.839 0.042 ;
    END
  END rw0_rd_out[90]
  PIN rw0_rd_out[91]
    DIRECTION OUTPUT ;
    USE SIGNAL ;
    SHAPE ABUTMENT ;
    PORT
      LAYER M3 ;
      RECT 98.273 0.000 98.287 0.042 ;
    END
  END rw0_rd_out[91]
  PIN rw0_rd_out[92]
    DIRECTION OUTPUT ;
    USE SIGNAL ;
    SHAPE ABUTMENT ;
    PORT
      LAYER M3 ;
      RECT 98.721 0.000 98.735 0.042 ;
    END
  END rw0_rd_out[92]
  PIN rw0_rd_out[93]
    DIRECTION OUTPUT ;
    USE SIGNAL ;
    SHAPE ABUTMENT ;
    PORT
      LAYER M3 ;
      RECT 99.169 0.000 99.183 0.042 ;
    END
  END rw0_rd_out[93]
  PIN rw0_rd_out[94]
    DIRECTION OUTPUT ;
    USE SIGNAL ;
    SHAPE ABUTMENT ;
    PORT
      LAYER M3 ;
      RECT 99.617 0.000 99.631 0.042 ;
    END
  END rw0_rd_out[94]
  PIN rw0_rd_out[95]
    DIRECTION OUTPUT ;
    USE SIGNAL ;
    SHAPE ABUTMENT ;
    PORT
      LAYER M3 ;
      RECT 100.065 0.000 100.079 0.042 ;
    END
  END rw0_rd_out[95]
  PIN rw0_rd_out[96]
    DIRECTION OUTPUT ;
    USE SIGNAL ;
    SHAPE ABUTMENT ;
    PORT
      LAYER M3 ;
      RECT 100.513 0.000 100.527 0.042 ;
    END
  END rw0_rd_out[96]
  PIN rw0_rd_out[97]
    DIRECTION OUTPUT ;
    USE SIGNAL ;
    SHAPE ABUTMENT ;
    PORT
      LAYER M3 ;
      RECT 100.961 0.000 100.975 0.042 ;
    END
  END rw0_rd_out[97]
  PIN rw0_rd_out[98]
    DIRECTION OUTPUT ;
    USE SIGNAL ;
    SHAPE ABUTMENT ;
    PORT
      LAYER M3 ;
      RECT 101.409 0.000 101.423 0.042 ;
    END
  END rw0_rd_out[98]
  PIN rw0_rd_out[99]
    DIRECTION OUTPUT ;
    USE SIGNAL ;
    SHAPE ABUTMENT ;
    PORT
      LAYER M3 ;
      RECT 101.857 0.000 101.871 0.042 ;
    END
  END rw0_rd_out[99]
  PIN rw0_rd_out[100]
    DIRECTION OUTPUT ;
    USE SIGNAL ;
    SHAPE ABUTMENT ;
    PORT
      LAYER M3 ;
      RECT 102.305 0.000 102.319 0.042 ;
    END
  END rw0_rd_out[100]
  PIN rw0_rd_out[101]
    DIRECTION OUTPUT ;
    USE SIGNAL ;
    SHAPE ABUTMENT ;
    PORT
      LAYER M3 ;
      RECT 102.753 0.000 102.767 0.042 ;
    END
  END rw0_rd_out[101]
  PIN rw0_rd_out[102]
    DIRECTION OUTPUT ;
    USE SIGNAL ;
    SHAPE ABUTMENT ;
    PORT
      LAYER M3 ;
      RECT 103.201 0.000 103.215 0.042 ;
    END
  END rw0_rd_out[102]
  PIN rw0_rd_out[103]
    DIRECTION OUTPUT ;
    USE SIGNAL ;
    SHAPE ABUTMENT ;
    PORT
      LAYER M3 ;
      RECT 103.649 0.000 103.663 0.042 ;
    END
  END rw0_rd_out[103]
  PIN rw0_rd_out[104]
    DIRECTION OUTPUT ;
    USE SIGNAL ;
    SHAPE ABUTMENT ;
    PORT
      LAYER M3 ;
      RECT 104.097 0.000 104.111 0.042 ;
    END
  END rw0_rd_out[104]
  PIN rw0_rd_out[105]
    DIRECTION OUTPUT ;
    USE SIGNAL ;
    SHAPE ABUTMENT ;
    PORT
      LAYER M3 ;
      RECT 104.545 0.000 104.559 0.042 ;
    END
  END rw0_rd_out[105]
  PIN rw0_rd_out[106]
    DIRECTION OUTPUT ;
    USE SIGNAL ;
    SHAPE ABUTMENT ;
    PORT
      LAYER M3 ;
      RECT 104.993 0.000 105.007 0.042 ;
    END
  END rw0_rd_out[106]
  PIN rw0_rd_out[107]
    DIRECTION OUTPUT ;
    USE SIGNAL ;
    SHAPE ABUTMENT ;
    PORT
      LAYER M3 ;
      RECT 105.441 0.000 105.455 0.042 ;
    END
  END rw0_rd_out[107]
  PIN rw0_rd_out[108]
    DIRECTION OUTPUT ;
    USE SIGNAL ;
    SHAPE ABUTMENT ;
    PORT
      LAYER M3 ;
      RECT 105.889 0.000 105.903 0.042 ;
    END
  END rw0_rd_out[108]
  PIN rw0_rd_out[109]
    DIRECTION OUTPUT ;
    USE SIGNAL ;
    SHAPE ABUTMENT ;
    PORT
      LAYER M3 ;
      RECT 106.337 0.000 106.351 0.042 ;
    END
  END rw0_rd_out[109]
  PIN rw0_rd_out[110]
    DIRECTION OUTPUT ;
    USE SIGNAL ;
    SHAPE ABUTMENT ;
    PORT
      LAYER M3 ;
      RECT 106.785 0.000 106.799 0.042 ;
    END
  END rw0_rd_out[110]
  PIN rw0_rd_out[111]
    DIRECTION OUTPUT ;
    USE SIGNAL ;
    SHAPE ABUTMENT ;
    PORT
      LAYER M3 ;
      RECT 107.233 0.000 107.247 0.042 ;
    END
  END rw0_rd_out[111]
  PIN rw0_rd_out[112]
    DIRECTION OUTPUT ;
    USE SIGNAL ;
    SHAPE ABUTMENT ;
    PORT
      LAYER M3 ;
      RECT 107.681 0.000 107.695 0.042 ;
    END
  END rw0_rd_out[112]
  PIN rw0_rd_out[113]
    DIRECTION OUTPUT ;
    USE SIGNAL ;
    SHAPE ABUTMENT ;
    PORT
      LAYER M3 ;
      RECT 108.129 0.000 108.143 0.042 ;
    END
  END rw0_rd_out[113]
  PIN rw0_rd_out[114]
    DIRECTION OUTPUT ;
    USE SIGNAL ;
    SHAPE ABUTMENT ;
    PORT
      LAYER M3 ;
      RECT 108.577 0.000 108.591 0.042 ;
    END
  END rw0_rd_out[114]
  PIN rw0_rd_out[115]
    DIRECTION OUTPUT ;
    USE SIGNAL ;
    SHAPE ABUTMENT ;
    PORT
      LAYER M3 ;
      RECT 109.025 0.000 109.039 0.042 ;
    END
  END rw0_rd_out[115]
  PIN rw0_rd_out[116]
    DIRECTION OUTPUT ;
    USE SIGNAL ;
    SHAPE ABUTMENT ;
    PORT
      LAYER M3 ;
      RECT 109.473 0.000 109.487 0.042 ;
    END
  END rw0_rd_out[116]
  PIN rw0_rd_out[117]
    DIRECTION OUTPUT ;
    USE SIGNAL ;
    SHAPE ABUTMENT ;
    PORT
      LAYER M3 ;
      RECT 109.921 0.000 109.935 0.042 ;
    END
  END rw0_rd_out[117]
  PIN rw0_rd_out[118]
    DIRECTION OUTPUT ;
    USE SIGNAL ;
    SHAPE ABUTMENT ;
    PORT
      LAYER M3 ;
      RECT 110.369 0.000 110.383 0.042 ;
    END
  END rw0_rd_out[118]
  PIN rw0_rd_out[119]
    DIRECTION OUTPUT ;
    USE SIGNAL ;
    SHAPE ABUTMENT ;
    PORT
      LAYER M3 ;
      RECT 110.817 0.000 110.831 0.042 ;
    END
  END rw0_rd_out[119]
  PIN rw0_rd_out[120]
    DIRECTION OUTPUT ;
    USE SIGNAL ;
    SHAPE ABUTMENT ;
    PORT
      LAYER M3 ;
      RECT 111.265 0.000 111.279 0.042 ;
    END
  END rw0_rd_out[120]
  PIN rw0_rd_out[121]
    DIRECTION OUTPUT ;
    USE SIGNAL ;
    SHAPE ABUTMENT ;
    PORT
      LAYER M3 ;
      RECT 111.713 0.000 111.727 0.042 ;
    END
  END rw0_rd_out[121]
  PIN rw0_rd_out[122]
    DIRECTION OUTPUT ;
    USE SIGNAL ;
    SHAPE ABUTMENT ;
    PORT
      LAYER M3 ;
      RECT 112.161 0.000 112.175 0.042 ;
    END
  END rw0_rd_out[122]
  PIN rw0_rd_out[123]
    DIRECTION OUTPUT ;
    USE SIGNAL ;
    SHAPE ABUTMENT ;
    PORT
      LAYER M3 ;
      RECT 112.609 0.000 112.623 0.042 ;
    END
  END rw0_rd_out[123]
  PIN rw0_rd_out[124]
    DIRECTION OUTPUT ;
    USE SIGNAL ;
    SHAPE ABUTMENT ;
    PORT
      LAYER M3 ;
      RECT 113.057 0.000 113.071 0.042 ;
    END
  END rw0_rd_out[124]
  PIN rw0_rd_out[125]
    DIRECTION OUTPUT ;
    USE SIGNAL ;
    SHAPE ABUTMENT ;
    PORT
      LAYER M3 ;
      RECT 113.505 0.000 113.519 0.042 ;
    END
  END rw0_rd_out[125]
  PIN rw0_rd_out[126]
    DIRECTION OUTPUT ;
    USE SIGNAL ;
    SHAPE ABUTMENT ;
    PORT
      LAYER M3 ;
      RECT 113.953 0.000 113.967 0.042 ;
    END
  END rw0_rd_out[126]
  PIN rw0_rd_out[127]
    DIRECTION OUTPUT ;
    USE SIGNAL ;
    SHAPE ABUTMENT ;
    PORT
      LAYER M3 ;
      RECT 114.401 0.000 114.415 0.042 ;
    END
  END rw0_rd_out[127]
  PIN rw0_rd_out[128]
    DIRECTION OUTPUT ;
    USE SIGNAL ;
    SHAPE ABUTMENT ;
    PORT
      LAYER M3 ;
      RECT 0.161 73.398 0.175 73.440 ;
    END
  END rw0_rd_out[128]
  PIN rw0_rd_out[129]
    DIRECTION OUTPUT ;
    USE SIGNAL ;
    SHAPE ABUTMENT ;
    PORT
      LAYER M3 ;
      RECT 1.029 73.398 1.043 73.440 ;
    END
  END rw0_rd_out[129]
  PIN rw0_rd_out[130]
    DIRECTION OUTPUT ;
    USE SIGNAL ;
    SHAPE ABUTMENT ;
    PORT
      LAYER M3 ;
      RECT 1.897 73.398 1.911 73.440 ;
    END
  END rw0_rd_out[130]
  PIN rw0_rd_out[131]
    DIRECTION OUTPUT ;
    USE SIGNAL ;
    SHAPE ABUTMENT ;
    PORT
      LAYER M3 ;
      RECT 2.765 73.398 2.779 73.440 ;
    END
  END rw0_rd_out[131]
  PIN rw0_rd_out[132]
    DIRECTION OUTPUT ;
    USE SIGNAL ;
    SHAPE ABUTMENT ;
    PORT
      LAYER M3 ;
      RECT 3.633 73.398 3.647 73.440 ;
    END
  END rw0_rd_out[132]
  PIN rw0_rd_out[133]
    DIRECTION OUTPUT ;
    USE SIGNAL ;
    SHAPE ABUTMENT ;
    PORT
      LAYER M3 ;
      RECT 4.501 73.398 4.515 73.440 ;
    END
  END rw0_rd_out[133]
  PIN rw0_rd_out[134]
    DIRECTION OUTPUT ;
    USE SIGNAL ;
    SHAPE ABUTMENT ;
    PORT
      LAYER M3 ;
      RECT 5.369 73.398 5.383 73.440 ;
    END
  END rw0_rd_out[134]
  PIN rw0_rd_out[135]
    DIRECTION OUTPUT ;
    USE SIGNAL ;
    SHAPE ABUTMENT ;
    PORT
      LAYER M3 ;
      RECT 6.237 73.398 6.251 73.440 ;
    END
  END rw0_rd_out[135]
  PIN rw0_rd_out[136]
    DIRECTION OUTPUT ;
    USE SIGNAL ;
    SHAPE ABUTMENT ;
    PORT
      LAYER M3 ;
      RECT 7.105 73.398 7.119 73.440 ;
    END
  END rw0_rd_out[136]
  PIN rw0_rd_out[137]
    DIRECTION OUTPUT ;
    USE SIGNAL ;
    SHAPE ABUTMENT ;
    PORT
      LAYER M3 ;
      RECT 7.973 73.398 7.987 73.440 ;
    END
  END rw0_rd_out[137]
  PIN rw0_rd_out[138]
    DIRECTION OUTPUT ;
    USE SIGNAL ;
    SHAPE ABUTMENT ;
    PORT
      LAYER M3 ;
      RECT 8.841 73.398 8.855 73.440 ;
    END
  END rw0_rd_out[138]
  PIN rw0_rd_out[139]
    DIRECTION OUTPUT ;
    USE SIGNAL ;
    SHAPE ABUTMENT ;
    PORT
      LAYER M3 ;
      RECT 9.709 73.398 9.723 73.440 ;
    END
  END rw0_rd_out[139]
  PIN rw0_rd_out[140]
    DIRECTION OUTPUT ;
    USE SIGNAL ;
    SHAPE ABUTMENT ;
    PORT
      LAYER M3 ;
      RECT 10.577 73.398 10.591 73.440 ;
    END
  END rw0_rd_out[140]
  PIN rw0_rd_out[141]
    DIRECTION OUTPUT ;
    USE SIGNAL ;
    SHAPE ABUTMENT ;
    PORT
      LAYER M3 ;
      RECT 11.445 73.398 11.459 73.440 ;
    END
  END rw0_rd_out[141]
  PIN rw0_rd_out[142]
    DIRECTION OUTPUT ;
    USE SIGNAL ;
    SHAPE ABUTMENT ;
    PORT
      LAYER M3 ;
      RECT 12.313 73.398 12.327 73.440 ;
    END
  END rw0_rd_out[142]
  PIN rw0_rd_out[143]
    DIRECTION OUTPUT ;
    USE SIGNAL ;
    SHAPE ABUTMENT ;
    PORT
      LAYER M3 ;
      RECT 13.181 73.398 13.195 73.440 ;
    END
  END rw0_rd_out[143]
  PIN rw0_rd_out[144]
    DIRECTION OUTPUT ;
    USE SIGNAL ;
    SHAPE ABUTMENT ;
    PORT
      LAYER M3 ;
      RECT 14.049 73.398 14.063 73.440 ;
    END
  END rw0_rd_out[144]
  PIN rw0_rd_out[145]
    DIRECTION OUTPUT ;
    USE SIGNAL ;
    SHAPE ABUTMENT ;
    PORT
      LAYER M3 ;
      RECT 14.917 73.398 14.931 73.440 ;
    END
  END rw0_rd_out[145]
  PIN rw0_rd_out[146]
    DIRECTION OUTPUT ;
    USE SIGNAL ;
    SHAPE ABUTMENT ;
    PORT
      LAYER M3 ;
      RECT 15.785 73.398 15.799 73.440 ;
    END
  END rw0_rd_out[146]
  PIN rw0_rd_out[147]
    DIRECTION OUTPUT ;
    USE SIGNAL ;
    SHAPE ABUTMENT ;
    PORT
      LAYER M3 ;
      RECT 16.653 73.398 16.667 73.440 ;
    END
  END rw0_rd_out[147]
  PIN rw0_rd_out[148]
    DIRECTION OUTPUT ;
    USE SIGNAL ;
    SHAPE ABUTMENT ;
    PORT
      LAYER M3 ;
      RECT 17.521 73.398 17.535 73.440 ;
    END
  END rw0_rd_out[148]
  PIN rw0_rd_out[149]
    DIRECTION OUTPUT ;
    USE SIGNAL ;
    SHAPE ABUTMENT ;
    PORT
      LAYER M3 ;
      RECT 18.389 73.398 18.403 73.440 ;
    END
  END rw0_rd_out[149]
  PIN rw0_rd_out[150]
    DIRECTION OUTPUT ;
    USE SIGNAL ;
    SHAPE ABUTMENT ;
    PORT
      LAYER M3 ;
      RECT 19.257 73.398 19.271 73.440 ;
    END
  END rw0_rd_out[150]
  PIN rw0_rd_out[151]
    DIRECTION OUTPUT ;
    USE SIGNAL ;
    SHAPE ABUTMENT ;
    PORT
      LAYER M3 ;
      RECT 20.125 73.398 20.139 73.440 ;
    END
  END rw0_rd_out[151]
  PIN rw0_rd_out[152]
    DIRECTION OUTPUT ;
    USE SIGNAL ;
    SHAPE ABUTMENT ;
    PORT
      LAYER M3 ;
      RECT 20.993 73.398 21.007 73.440 ;
    END
  END rw0_rd_out[152]
  PIN rw0_rd_out[153]
    DIRECTION OUTPUT ;
    USE SIGNAL ;
    SHAPE ABUTMENT ;
    PORT
      LAYER M3 ;
      RECT 21.861 73.398 21.875 73.440 ;
    END
  END rw0_rd_out[153]
  PIN rw0_rd_out[154]
    DIRECTION OUTPUT ;
    USE SIGNAL ;
    SHAPE ABUTMENT ;
    PORT
      LAYER M3 ;
      RECT 22.729 73.398 22.743 73.440 ;
    END
  END rw0_rd_out[154]
  PIN rw0_rd_out[155]
    DIRECTION OUTPUT ;
    USE SIGNAL ;
    SHAPE ABUTMENT ;
    PORT
      LAYER M3 ;
      RECT 23.597 73.398 23.611 73.440 ;
    END
  END rw0_rd_out[155]
  PIN rw0_rd_out[156]
    DIRECTION OUTPUT ;
    USE SIGNAL ;
    SHAPE ABUTMENT ;
    PORT
      LAYER M3 ;
      RECT 24.465 73.398 24.479 73.440 ;
    END
  END rw0_rd_out[156]
  PIN rw0_rd_out[157]
    DIRECTION OUTPUT ;
    USE SIGNAL ;
    SHAPE ABUTMENT ;
    PORT
      LAYER M3 ;
      RECT 25.333 73.398 25.347 73.440 ;
    END
  END rw0_rd_out[157]
  PIN rw0_rd_out[158]
    DIRECTION OUTPUT ;
    USE SIGNAL ;
    SHAPE ABUTMENT ;
    PORT
      LAYER M3 ;
      RECT 26.201 73.398 26.215 73.440 ;
    END
  END rw0_rd_out[158]
  PIN rw0_rd_out[159]
    DIRECTION OUTPUT ;
    USE SIGNAL ;
    SHAPE ABUTMENT ;
    PORT
      LAYER M3 ;
      RECT 27.069 73.398 27.083 73.440 ;
    END
  END rw0_rd_out[159]
  PIN rw0_rd_out[160]
    DIRECTION OUTPUT ;
    USE SIGNAL ;
    SHAPE ABUTMENT ;
    PORT
      LAYER M3 ;
      RECT 27.937 73.398 27.951 73.440 ;
    END
  END rw0_rd_out[160]
  PIN rw0_rd_out[161]
    DIRECTION OUTPUT ;
    USE SIGNAL ;
    SHAPE ABUTMENT ;
    PORT
      LAYER M3 ;
      RECT 28.805 73.398 28.819 73.440 ;
    END
  END rw0_rd_out[161]
  PIN rw0_rd_out[162]
    DIRECTION OUTPUT ;
    USE SIGNAL ;
    SHAPE ABUTMENT ;
    PORT
      LAYER M3 ;
      RECT 29.673 73.398 29.687 73.440 ;
    END
  END rw0_rd_out[162]
  PIN rw0_rd_out[163]
    DIRECTION OUTPUT ;
    USE SIGNAL ;
    SHAPE ABUTMENT ;
    PORT
      LAYER M3 ;
      RECT 30.541 73.398 30.555 73.440 ;
    END
  END rw0_rd_out[163]
  PIN rw0_rd_out[164]
    DIRECTION OUTPUT ;
    USE SIGNAL ;
    SHAPE ABUTMENT ;
    PORT
      LAYER M3 ;
      RECT 31.409 73.398 31.423 73.440 ;
    END
  END rw0_rd_out[164]
  PIN rw0_rd_out[165]
    DIRECTION OUTPUT ;
    USE SIGNAL ;
    SHAPE ABUTMENT ;
    PORT
      LAYER M3 ;
      RECT 32.277 73.398 32.291 73.440 ;
    END
  END rw0_rd_out[165]
  PIN rw0_rd_out[166]
    DIRECTION OUTPUT ;
    USE SIGNAL ;
    SHAPE ABUTMENT ;
    PORT
      LAYER M3 ;
      RECT 33.145 73.398 33.159 73.440 ;
    END
  END rw0_rd_out[166]
  PIN rw0_rd_out[167]
    DIRECTION OUTPUT ;
    USE SIGNAL ;
    SHAPE ABUTMENT ;
    PORT
      LAYER M3 ;
      RECT 34.013 73.398 34.027 73.440 ;
    END
  END rw0_rd_out[167]
  PIN rw0_rd_out[168]
    DIRECTION OUTPUT ;
    USE SIGNAL ;
    SHAPE ABUTMENT ;
    PORT
      LAYER M3 ;
      RECT 34.881 73.398 34.895 73.440 ;
    END
  END rw0_rd_out[168]
  PIN rw0_rd_out[169]
    DIRECTION OUTPUT ;
    USE SIGNAL ;
    SHAPE ABUTMENT ;
    PORT
      LAYER M3 ;
      RECT 35.749 73.398 35.763 73.440 ;
    END
  END rw0_rd_out[169]
  PIN rw0_rd_out[170]
    DIRECTION OUTPUT ;
    USE SIGNAL ;
    SHAPE ABUTMENT ;
    PORT
      LAYER M3 ;
      RECT 36.617 73.398 36.631 73.440 ;
    END
  END rw0_rd_out[170]
  PIN rw0_rd_out[171]
    DIRECTION OUTPUT ;
    USE SIGNAL ;
    SHAPE ABUTMENT ;
    PORT
      LAYER M3 ;
      RECT 37.485 73.398 37.499 73.440 ;
    END
  END rw0_rd_out[171]
  PIN rw0_rd_out[172]
    DIRECTION OUTPUT ;
    USE SIGNAL ;
    SHAPE ABUTMENT ;
    PORT
      LAYER M3 ;
      RECT 38.353 73.398 38.367 73.440 ;
    END
  END rw0_rd_out[172]
  PIN rw0_rd_out[173]
    DIRECTION OUTPUT ;
    USE SIGNAL ;
    SHAPE ABUTMENT ;
    PORT
      LAYER M3 ;
      RECT 39.221 73.398 39.235 73.440 ;
    END
  END rw0_rd_out[173]
  PIN rw0_rd_out[174]
    DIRECTION OUTPUT ;
    USE SIGNAL ;
    SHAPE ABUTMENT ;
    PORT
      LAYER M3 ;
      RECT 40.089 73.398 40.103 73.440 ;
    END
  END rw0_rd_out[174]
  PIN rw0_rd_out[175]
    DIRECTION OUTPUT ;
    USE SIGNAL ;
    SHAPE ABUTMENT ;
    PORT
      LAYER M3 ;
      RECT 40.957 73.398 40.971 73.440 ;
    END
  END rw0_rd_out[175]
  PIN rw0_rd_out[176]
    DIRECTION OUTPUT ;
    USE SIGNAL ;
    SHAPE ABUTMENT ;
    PORT
      LAYER M3 ;
      RECT 41.825 73.398 41.839 73.440 ;
    END
  END rw0_rd_out[176]
  PIN rw0_rd_out[177]
    DIRECTION OUTPUT ;
    USE SIGNAL ;
    SHAPE ABUTMENT ;
    PORT
      LAYER M3 ;
      RECT 42.693 73.398 42.707 73.440 ;
    END
  END rw0_rd_out[177]
  PIN rw0_rd_out[178]
    DIRECTION OUTPUT ;
    USE SIGNAL ;
    SHAPE ABUTMENT ;
    PORT
      LAYER M3 ;
      RECT 43.561 73.398 43.575 73.440 ;
    END
  END rw0_rd_out[178]
  PIN rw0_rd_out[179]
    DIRECTION OUTPUT ;
    USE SIGNAL ;
    SHAPE ABUTMENT ;
    PORT
      LAYER M3 ;
      RECT 44.429 73.398 44.443 73.440 ;
    END
  END rw0_rd_out[179]
  PIN rw0_rd_out[180]
    DIRECTION OUTPUT ;
    USE SIGNAL ;
    SHAPE ABUTMENT ;
    PORT
      LAYER M3 ;
      RECT 45.297 73.398 45.311 73.440 ;
    END
  END rw0_rd_out[180]
  PIN rw0_rd_out[181]
    DIRECTION OUTPUT ;
    USE SIGNAL ;
    SHAPE ABUTMENT ;
    PORT
      LAYER M3 ;
      RECT 46.165 73.398 46.179 73.440 ;
    END
  END rw0_rd_out[181]
  PIN rw0_rd_out[182]
    DIRECTION OUTPUT ;
    USE SIGNAL ;
    SHAPE ABUTMENT ;
    PORT
      LAYER M3 ;
      RECT 47.033 73.398 47.047 73.440 ;
    END
  END rw0_rd_out[182]
  PIN rw0_rd_out[183]
    DIRECTION OUTPUT ;
    USE SIGNAL ;
    SHAPE ABUTMENT ;
    PORT
      LAYER M3 ;
      RECT 47.901 73.398 47.915 73.440 ;
    END
  END rw0_rd_out[183]
  PIN rw0_rd_out[184]
    DIRECTION OUTPUT ;
    USE SIGNAL ;
    SHAPE ABUTMENT ;
    PORT
      LAYER M3 ;
      RECT 48.769 73.398 48.783 73.440 ;
    END
  END rw0_rd_out[184]
  PIN rw0_rd_out[185]
    DIRECTION OUTPUT ;
    USE SIGNAL ;
    SHAPE ABUTMENT ;
    PORT
      LAYER M3 ;
      RECT 49.637 73.398 49.651 73.440 ;
    END
  END rw0_rd_out[185]
  PIN rw0_rd_out[186]
    DIRECTION OUTPUT ;
    USE SIGNAL ;
    SHAPE ABUTMENT ;
    PORT
      LAYER M3 ;
      RECT 50.505 73.398 50.519 73.440 ;
    END
  END rw0_rd_out[186]
  PIN rw0_rd_out[187]
    DIRECTION OUTPUT ;
    USE SIGNAL ;
    SHAPE ABUTMENT ;
    PORT
      LAYER M3 ;
      RECT 51.373 73.398 51.387 73.440 ;
    END
  END rw0_rd_out[187]
  PIN rw0_rd_out[188]
    DIRECTION OUTPUT ;
    USE SIGNAL ;
    SHAPE ABUTMENT ;
    PORT
      LAYER M3 ;
      RECT 52.241 73.398 52.255 73.440 ;
    END
  END rw0_rd_out[188]
  PIN rw0_rd_out[189]
    DIRECTION OUTPUT ;
    USE SIGNAL ;
    SHAPE ABUTMENT ;
    PORT
      LAYER M3 ;
      RECT 53.109 73.398 53.123 73.440 ;
    END
  END rw0_rd_out[189]
  PIN rw0_rd_out[190]
    DIRECTION OUTPUT ;
    USE SIGNAL ;
    SHAPE ABUTMENT ;
    PORT
      LAYER M3 ;
      RECT 53.977 73.398 53.991 73.440 ;
    END
  END rw0_rd_out[190]
  PIN rw0_rd_out[191]
    DIRECTION OUTPUT ;
    USE SIGNAL ;
    SHAPE ABUTMENT ;
    PORT
      LAYER M3 ;
      RECT 54.845 73.398 54.859 73.440 ;
    END
  END rw0_rd_out[191]
  PIN rw0_rd_out[192]
    DIRECTION OUTPUT ;
    USE SIGNAL ;
    SHAPE ABUTMENT ;
    PORT
      LAYER M3 ;
      RECT 55.713 73.398 55.727 73.440 ;
    END
  END rw0_rd_out[192]
  PIN rw0_rd_out[193]
    DIRECTION OUTPUT ;
    USE SIGNAL ;
    SHAPE ABUTMENT ;
    PORT
      LAYER M3 ;
      RECT 56.581 73.398 56.595 73.440 ;
    END
  END rw0_rd_out[193]
  PIN rw0_rd_out[194]
    DIRECTION OUTPUT ;
    USE SIGNAL ;
    SHAPE ABUTMENT ;
    PORT
      LAYER M3 ;
      RECT 57.449 73.398 57.463 73.440 ;
    END
  END rw0_rd_out[194]
  PIN rw0_rd_out[195]
    DIRECTION OUTPUT ;
    USE SIGNAL ;
    SHAPE ABUTMENT ;
    PORT
      LAYER M3 ;
      RECT 58.317 73.398 58.331 73.440 ;
    END
  END rw0_rd_out[195]
  PIN rw0_rd_out[196]
    DIRECTION OUTPUT ;
    USE SIGNAL ;
    SHAPE ABUTMENT ;
    PORT
      LAYER M3 ;
      RECT 59.185 73.398 59.199 73.440 ;
    END
  END rw0_rd_out[196]
  PIN rw0_rd_out[197]
    DIRECTION OUTPUT ;
    USE SIGNAL ;
    SHAPE ABUTMENT ;
    PORT
      LAYER M3 ;
      RECT 60.053 73.398 60.067 73.440 ;
    END
  END rw0_rd_out[197]
  PIN rw0_rd_out[198]
    DIRECTION OUTPUT ;
    USE SIGNAL ;
    SHAPE ABUTMENT ;
    PORT
      LAYER M3 ;
      RECT 60.921 73.398 60.935 73.440 ;
    END
  END rw0_rd_out[198]
  PIN rw0_rd_out[199]
    DIRECTION OUTPUT ;
    USE SIGNAL ;
    SHAPE ABUTMENT ;
    PORT
      LAYER M3 ;
      RECT 61.789 73.398 61.803 73.440 ;
    END
  END rw0_rd_out[199]
  PIN rw0_rd_out[200]
    DIRECTION OUTPUT ;
    USE SIGNAL ;
    SHAPE ABUTMENT ;
    PORT
      LAYER M3 ;
      RECT 62.657 73.398 62.671 73.440 ;
    END
  END rw0_rd_out[200]
  PIN rw0_rd_out[201]
    DIRECTION OUTPUT ;
    USE SIGNAL ;
    SHAPE ABUTMENT ;
    PORT
      LAYER M3 ;
      RECT 63.525 73.398 63.539 73.440 ;
    END
  END rw0_rd_out[201]
  PIN rw0_rd_out[202]
    DIRECTION OUTPUT ;
    USE SIGNAL ;
    SHAPE ABUTMENT ;
    PORT
      LAYER M3 ;
      RECT 64.393 73.398 64.407 73.440 ;
    END
  END rw0_rd_out[202]
  PIN rw0_rd_out[203]
    DIRECTION OUTPUT ;
    USE SIGNAL ;
    SHAPE ABUTMENT ;
    PORT
      LAYER M3 ;
      RECT 65.261 73.398 65.275 73.440 ;
    END
  END rw0_rd_out[203]
  PIN rw0_rd_out[204]
    DIRECTION OUTPUT ;
    USE SIGNAL ;
    SHAPE ABUTMENT ;
    PORT
      LAYER M3 ;
      RECT 66.129 73.398 66.143 73.440 ;
    END
  END rw0_rd_out[204]
  PIN rw0_rd_out[205]
    DIRECTION OUTPUT ;
    USE SIGNAL ;
    SHAPE ABUTMENT ;
    PORT
      LAYER M3 ;
      RECT 66.997 73.398 67.011 73.440 ;
    END
  END rw0_rd_out[205]
  PIN rw0_rd_out[206]
    DIRECTION OUTPUT ;
    USE SIGNAL ;
    SHAPE ABUTMENT ;
    PORT
      LAYER M3 ;
      RECT 67.865 73.398 67.879 73.440 ;
    END
  END rw0_rd_out[206]
  PIN rw0_rd_out[207]
    DIRECTION OUTPUT ;
    USE SIGNAL ;
    SHAPE ABUTMENT ;
    PORT
      LAYER M3 ;
      RECT 68.733 73.398 68.747 73.440 ;
    END
  END rw0_rd_out[207]
  PIN rw0_rd_out[208]
    DIRECTION OUTPUT ;
    USE SIGNAL ;
    SHAPE ABUTMENT ;
    PORT
      LAYER M3 ;
      RECT 69.601 73.398 69.615 73.440 ;
    END
  END rw0_rd_out[208]
  PIN rw0_rd_out[209]
    DIRECTION OUTPUT ;
    USE SIGNAL ;
    SHAPE ABUTMENT ;
    PORT
      LAYER M3 ;
      RECT 70.469 73.398 70.483 73.440 ;
    END
  END rw0_rd_out[209]
  PIN rw0_rd_out[210]
    DIRECTION OUTPUT ;
    USE SIGNAL ;
    SHAPE ABUTMENT ;
    PORT
      LAYER M3 ;
      RECT 71.337 73.398 71.351 73.440 ;
    END
  END rw0_rd_out[210]
  PIN rw0_rd_out[211]
    DIRECTION OUTPUT ;
    USE SIGNAL ;
    SHAPE ABUTMENT ;
    PORT
      LAYER M3 ;
      RECT 72.205 73.398 72.219 73.440 ;
    END
  END rw0_rd_out[211]
  PIN rw0_rd_out[212]
    DIRECTION OUTPUT ;
    USE SIGNAL ;
    SHAPE ABUTMENT ;
    PORT
      LAYER M3 ;
      RECT 73.073 73.398 73.087 73.440 ;
    END
  END rw0_rd_out[212]
  PIN rw0_rd_out[213]
    DIRECTION OUTPUT ;
    USE SIGNAL ;
    SHAPE ABUTMENT ;
    PORT
      LAYER M3 ;
      RECT 73.941 73.398 73.955 73.440 ;
    END
  END rw0_rd_out[213]
  PIN rw0_rd_out[214]
    DIRECTION OUTPUT ;
    USE SIGNAL ;
    SHAPE ABUTMENT ;
    PORT
      LAYER M3 ;
      RECT 74.809 73.398 74.823 73.440 ;
    END
  END rw0_rd_out[214]
  PIN rw0_rd_out[215]
    DIRECTION OUTPUT ;
    USE SIGNAL ;
    SHAPE ABUTMENT ;
    PORT
      LAYER M3 ;
      RECT 75.677 73.398 75.691 73.440 ;
    END
  END rw0_rd_out[215]
  PIN rw0_rd_out[216]
    DIRECTION OUTPUT ;
    USE SIGNAL ;
    SHAPE ABUTMENT ;
    PORT
      LAYER M3 ;
      RECT 76.545 73.398 76.559 73.440 ;
    END
  END rw0_rd_out[216]
  PIN rw0_rd_out[217]
    DIRECTION OUTPUT ;
    USE SIGNAL ;
    SHAPE ABUTMENT ;
    PORT
      LAYER M3 ;
      RECT 77.413 73.398 77.427 73.440 ;
    END
  END rw0_rd_out[217]
  PIN rw0_rd_out[218]
    DIRECTION OUTPUT ;
    USE SIGNAL ;
    SHAPE ABUTMENT ;
    PORT
      LAYER M3 ;
      RECT 78.281 73.398 78.295 73.440 ;
    END
  END rw0_rd_out[218]
  PIN rw0_rd_out[219]
    DIRECTION OUTPUT ;
    USE SIGNAL ;
    SHAPE ABUTMENT ;
    PORT
      LAYER M3 ;
      RECT 79.149 73.398 79.163 73.440 ;
    END
  END rw0_rd_out[219]
  PIN rw0_rd_out[220]
    DIRECTION OUTPUT ;
    USE SIGNAL ;
    SHAPE ABUTMENT ;
    PORT
      LAYER M3 ;
      RECT 80.017 73.398 80.031 73.440 ;
    END
  END rw0_rd_out[220]
  PIN rw0_rd_out[221]
    DIRECTION OUTPUT ;
    USE SIGNAL ;
    SHAPE ABUTMENT ;
    PORT
      LAYER M3 ;
      RECT 80.885 73.398 80.899 73.440 ;
    END
  END rw0_rd_out[221]
  PIN rw0_rd_out[222]
    DIRECTION OUTPUT ;
    USE SIGNAL ;
    SHAPE ABUTMENT ;
    PORT
      LAYER M3 ;
      RECT 81.753 73.398 81.767 73.440 ;
    END
  END rw0_rd_out[222]
  PIN rw0_rd_out[223]
    DIRECTION OUTPUT ;
    USE SIGNAL ;
    SHAPE ABUTMENT ;
    PORT
      LAYER M3 ;
      RECT 82.621 73.398 82.635 73.440 ;
    END
  END rw0_rd_out[223]
  PIN rw0_rd_out[224]
    DIRECTION OUTPUT ;
    USE SIGNAL ;
    SHAPE ABUTMENT ;
    PORT
      LAYER M3 ;
      RECT 83.489 73.398 83.503 73.440 ;
    END
  END rw0_rd_out[224]
  PIN rw0_rd_out[225]
    DIRECTION OUTPUT ;
    USE SIGNAL ;
    SHAPE ABUTMENT ;
    PORT
      LAYER M3 ;
      RECT 84.357 73.398 84.371 73.440 ;
    END
  END rw0_rd_out[225]
  PIN rw0_rd_out[226]
    DIRECTION OUTPUT ;
    USE SIGNAL ;
    SHAPE ABUTMENT ;
    PORT
      LAYER M3 ;
      RECT 85.225 73.398 85.239 73.440 ;
    END
  END rw0_rd_out[226]
  PIN rw0_rd_out[227]
    DIRECTION OUTPUT ;
    USE SIGNAL ;
    SHAPE ABUTMENT ;
    PORT
      LAYER M3 ;
      RECT 86.093 73.398 86.107 73.440 ;
    END
  END rw0_rd_out[227]
  PIN rw0_rd_out[228]
    DIRECTION OUTPUT ;
    USE SIGNAL ;
    SHAPE ABUTMENT ;
    PORT
      LAYER M3 ;
      RECT 86.961 73.398 86.975 73.440 ;
    END
  END rw0_rd_out[228]
  PIN rw0_rd_out[229]
    DIRECTION OUTPUT ;
    USE SIGNAL ;
    SHAPE ABUTMENT ;
    PORT
      LAYER M3 ;
      RECT 87.829 73.398 87.843 73.440 ;
    END
  END rw0_rd_out[229]
  PIN rw0_rd_out[230]
    DIRECTION OUTPUT ;
    USE SIGNAL ;
    SHAPE ABUTMENT ;
    PORT
      LAYER M3 ;
      RECT 88.697 73.398 88.711 73.440 ;
    END
  END rw0_rd_out[230]
  PIN rw0_rd_out[231]
    DIRECTION OUTPUT ;
    USE SIGNAL ;
    SHAPE ABUTMENT ;
    PORT
      LAYER M3 ;
      RECT 89.565 73.398 89.579 73.440 ;
    END
  END rw0_rd_out[231]
  PIN rw0_rd_out[232]
    DIRECTION OUTPUT ;
    USE SIGNAL ;
    SHAPE ABUTMENT ;
    PORT
      LAYER M3 ;
      RECT 90.433 73.398 90.447 73.440 ;
    END
  END rw0_rd_out[232]
  PIN rw0_rd_out[233]
    DIRECTION OUTPUT ;
    USE SIGNAL ;
    SHAPE ABUTMENT ;
    PORT
      LAYER M3 ;
      RECT 91.301 73.398 91.315 73.440 ;
    END
  END rw0_rd_out[233]
  PIN rw0_rd_out[234]
    DIRECTION OUTPUT ;
    USE SIGNAL ;
    SHAPE ABUTMENT ;
    PORT
      LAYER M3 ;
      RECT 92.169 73.398 92.183 73.440 ;
    END
  END rw0_rd_out[234]
  PIN rw0_rd_out[235]
    DIRECTION OUTPUT ;
    USE SIGNAL ;
    SHAPE ABUTMENT ;
    PORT
      LAYER M3 ;
      RECT 93.037 73.398 93.051 73.440 ;
    END
  END rw0_rd_out[235]
  PIN rw0_rd_out[236]
    DIRECTION OUTPUT ;
    USE SIGNAL ;
    SHAPE ABUTMENT ;
    PORT
      LAYER M3 ;
      RECT 93.905 73.398 93.919 73.440 ;
    END
  END rw0_rd_out[236]
  PIN rw0_rd_out[237]
    DIRECTION OUTPUT ;
    USE SIGNAL ;
    SHAPE ABUTMENT ;
    PORT
      LAYER M3 ;
      RECT 94.773 73.398 94.787 73.440 ;
    END
  END rw0_rd_out[237]
  PIN rw0_rd_out[238]
    DIRECTION OUTPUT ;
    USE SIGNAL ;
    SHAPE ABUTMENT ;
    PORT
      LAYER M3 ;
      RECT 95.641 73.398 95.655 73.440 ;
    END
  END rw0_rd_out[238]
  PIN rw0_rd_out[239]
    DIRECTION OUTPUT ;
    USE SIGNAL ;
    SHAPE ABUTMENT ;
    PORT
      LAYER M3 ;
      RECT 96.509 73.398 96.523 73.440 ;
    END
  END rw0_rd_out[239]
  PIN rw0_rd_out[240]
    DIRECTION OUTPUT ;
    USE SIGNAL ;
    SHAPE ABUTMENT ;
    PORT
      LAYER M3 ;
      RECT 97.377 73.398 97.391 73.440 ;
    END
  END rw0_rd_out[240]
  PIN rw0_rd_out[241]
    DIRECTION OUTPUT ;
    USE SIGNAL ;
    SHAPE ABUTMENT ;
    PORT
      LAYER M3 ;
      RECT 98.245 73.398 98.259 73.440 ;
    END
  END rw0_rd_out[241]
  PIN rw0_rd_out[242]
    DIRECTION OUTPUT ;
    USE SIGNAL ;
    SHAPE ABUTMENT ;
    PORT
      LAYER M3 ;
      RECT 99.113 73.398 99.127 73.440 ;
    END
  END rw0_rd_out[242]
  PIN rw0_rd_out[243]
    DIRECTION OUTPUT ;
    USE SIGNAL ;
    SHAPE ABUTMENT ;
    PORT
      LAYER M3 ;
      RECT 99.981 73.398 99.995 73.440 ;
    END
  END rw0_rd_out[243]
  PIN rw0_rd_out[244]
    DIRECTION OUTPUT ;
    USE SIGNAL ;
    SHAPE ABUTMENT ;
    PORT
      LAYER M3 ;
      RECT 100.849 73.398 100.863 73.440 ;
    END
  END rw0_rd_out[244]
  PIN rw0_rd_out[245]
    DIRECTION OUTPUT ;
    USE SIGNAL ;
    SHAPE ABUTMENT ;
    PORT
      LAYER M3 ;
      RECT 101.717 73.398 101.731 73.440 ;
    END
  END rw0_rd_out[245]
  PIN rw0_rd_out[246]
    DIRECTION OUTPUT ;
    USE SIGNAL ;
    SHAPE ABUTMENT ;
    PORT
      LAYER M3 ;
      RECT 102.585 73.398 102.599 73.440 ;
    END
  END rw0_rd_out[246]
  PIN rw0_rd_out[247]
    DIRECTION OUTPUT ;
    USE SIGNAL ;
    SHAPE ABUTMENT ;
    PORT
      LAYER M3 ;
      RECT 103.453 73.398 103.467 73.440 ;
    END
  END rw0_rd_out[247]
  PIN rw0_rd_out[248]
    DIRECTION OUTPUT ;
    USE SIGNAL ;
    SHAPE ABUTMENT ;
    PORT
      LAYER M3 ;
      RECT 104.321 73.398 104.335 73.440 ;
    END
  END rw0_rd_out[248]
  PIN rw0_rd_out[249]
    DIRECTION OUTPUT ;
    USE SIGNAL ;
    SHAPE ABUTMENT ;
    PORT
      LAYER M3 ;
      RECT 105.189 73.398 105.203 73.440 ;
    END
  END rw0_rd_out[249]
  PIN rw0_rd_out[250]
    DIRECTION OUTPUT ;
    USE SIGNAL ;
    SHAPE ABUTMENT ;
    PORT
      LAYER M3 ;
      RECT 106.057 73.398 106.071 73.440 ;
    END
  END rw0_rd_out[250]
  PIN rw0_rd_out[251]
    DIRECTION OUTPUT ;
    USE SIGNAL ;
    SHAPE ABUTMENT ;
    PORT
      LAYER M3 ;
      RECT 106.925 73.398 106.939 73.440 ;
    END
  END rw0_rd_out[251]
  PIN rw0_rd_out[252]
    DIRECTION OUTPUT ;
    USE SIGNAL ;
    SHAPE ABUTMENT ;
    PORT
      LAYER M3 ;
      RECT 107.793 73.398 107.807 73.440 ;
    END
  END rw0_rd_out[252]
  PIN rw0_rd_out[253]
    DIRECTION OUTPUT ;
    USE SIGNAL ;
    SHAPE ABUTMENT ;
    PORT
      LAYER M3 ;
      RECT 108.661 73.398 108.675 73.440 ;
    END
  END rw0_rd_out[253]
  PIN rw0_rd_out[254]
    DIRECTION OUTPUT ;
    USE SIGNAL ;
    SHAPE ABUTMENT ;
    PORT
      LAYER M3 ;
      RECT 109.529 73.398 109.543 73.440 ;
    END
  END rw0_rd_out[254]
  PIN rw0_rd_out[255]
    DIRECTION OUTPUT ;
    USE SIGNAL ;
    SHAPE ABUTMENT ;
    PORT
      LAYER M3 ;
      RECT 110.397 73.398 110.411 73.440 ;
    END
  END rw0_rd_out[255]
  PIN rw0_addr_in[0]
    DIRECTION INPUT ;
    USE SIGNAL ;
    SHAPE ABUTMENT ;
    PORT
      LAYER M2 ;
      RECT 0.000 67.722 0.036 67.734 ;
    END
  END rw0_addr_in[0]
  PIN rw0_addr_in[1]
    DIRECTION INPUT ;
    USE SIGNAL ;
    SHAPE ABUTMENT ;
    PORT
      LAYER M2 ;
      RECT 0.000 68.778 0.036 68.790 ;
    END
  END rw0_addr_in[1]
  PIN rw0_addr_in[2]
    DIRECTION INPUT ;
    USE SIGNAL ;
    SHAPE ABUTMENT ;
    PORT
      LAYER M2 ;
      RECT 0.000 69.834 0.036 69.846 ;
    END
  END rw0_addr_in[2]
  PIN rw0_addr_in[3]
    DIRECTION INPUT ;
    USE SIGNAL ;
    SHAPE ABUTMENT ;
    PORT
      LAYER M2 ;
      RECT 0.000 70.890 0.036 70.902 ;
    END
  END rw0_addr_in[3]
  PIN rw0_addr_in[4]
    DIRECTION INPUT ;
    USE SIGNAL ;
    SHAPE ABUTMENT ;
    PORT
      LAYER M2 ;
      RECT 117.354 67.722 117.390 67.734 ;
    END
  END rw0_addr_in[4]
  PIN rw0_addr_in[5]
    DIRECTION INPUT ;
    USE SIGNAL ;
    SHAPE ABUTMENT ;
    PORT
      LAYER M2 ;
      RECT 117.354 68.778 117.390 68.790 ;
    END
  END rw0_addr_in[5]
  PIN rw0_addr_in[6]
    DIRECTION INPUT ;
    USE SIGNAL ;
    SHAPE ABUTMENT ;
    PORT
      LAYER M2 ;
      RECT 117.354 69.834 117.390 69.846 ;
    END
  END rw0_addr_in[6]
  PIN rw0_addr_in[7]
    DIRECTION INPUT ;
    USE SIGNAL ;
    SHAPE ABUTMENT ;
    PORT
      LAYER M2 ;
      RECT 117.354 70.890 117.390 70.902 ;
    END
  END rw0_addr_in[7]
  PIN rw0_we_in
    DIRECTION INPUT ;
    USE SIGNAL ;
    SHAPE ABUTMENT ;
    PORT
      LAYER M3 ;
      RECT 111.265 73.398 111.279 73.440 ;
    END
  END rw0_we_in
  PIN rw0_ce_in
    DIRECTION INPUT ;
    USE SIGNAL ;
    SHAPE ABUTMENT ;
    PORT
      LAYER M3 ;
      RECT 112.133 73.398 112.147 73.440 ;
    END
  END rw0_ce_in
  PIN rw0_clk
    DIRECTION INPUT ;
    USE SIGNAL ;
    SHAPE ABUTMENT ;
    PORT
      LAYER M3 ;
      RECT 113.001 73.398 113.015 73.440 ;
    END
  END rw0_clk
  PIN VSS
    DIRECTION INOUT ;
    USE GROUND ;
    PORT
      LAYER M4 ;
      RECT 0.168 0.120 117.222 0.168 ;
      RECT 0.168 0.504 117.222 0.552 ;
      RECT 0.168 0.888 117.222 0.936 ;
      RECT 0.168 1.272 117.222 1.320 ;
      RECT 0.168 1.656 117.222 1.704 ;
      RECT 0.168 2.040 117.222 2.088 ;
      RECT 0.168 2.424 117.222 2.472 ;
      RECT 0.168 2.808 117.222 2.856 ;
      RECT 0.168 3.192 117.222 3.240 ;
      RECT 0.168 3.576 117.222 3.624 ;
      RECT 0.168 3.960 117.222 4.008 ;
      RECT 0.168 4.344 117.222 4.392 ;
      RECT 0.168 4.728 117.222 4.776 ;
      RECT 0.168 5.112 117.222 5.160 ;
      RECT 0.168 5.496 117.222 5.544 ;
      RECT 0.168 5.880 117.222 5.928 ;
      RECT 0.168 6.264 117.222 6.312 ;
      RECT 0.168 6.648 117.222 6.696 ;
      RECT 0.168 7.032 117.222 7.080 ;
      RECT 0.168 7.416 117.222 7.464 ;
      RECT 0.168 7.800 117.222 7.848 ;
      RECT 0.168 8.184 117.222 8.232 ;
      RECT 0.168 8.568 117.222 8.616 ;
      RECT 0.168 8.952 117.222 9.000 ;
      RECT 0.168 9.336 117.222 9.384 ;
      RECT 0.168 9.720 117.222 9.768 ;
      RECT 0.168 10.104 117.222 10.152 ;
      RECT 0.168 10.488 117.222 10.536 ;
      RECT 0.168 10.872 117.222 10.920 ;
      RECT 0.168 11.256 117.222 11.304 ;
      RECT 0.168 11.640 117.222 11.688 ;
      RECT 0.168 12.024 117.222 12.072 ;
      RECT 0.168 12.408 117.222 12.456 ;
      RECT 0.168 12.792 117.222 12.840 ;
      RECT 0.168 13.176 117.222 13.224 ;
      RECT 0.168 13.560 117.222 13.608 ;
      RECT 0.168 13.944 117.222 13.992 ;
      RECT 0.168 14.328 117.222 14.376 ;
      RECT 0.168 14.712 117.222 14.760 ;
      RECT 0.168 15.096 117.222 15.144 ;
      RECT 0.168 15.480 117.222 15.528 ;
      RECT 0.168 15.864 117.222 15.912 ;
      RECT 0.168 16.248 117.222 16.296 ;
      RECT 0.168 16.632 117.222 16.680 ;
      RECT 0.168 17.016 117.222 17.064 ;
      RECT 0.168 17.400 117.222 17.448 ;
      RECT 0.168 17.784 117.222 17.832 ;
      RECT 0.168 18.168 117.222 18.216 ;
      RECT 0.168 18.552 117.222 18.600 ;
      RECT 0.168 18.936 117.222 18.984 ;
      RECT 0.168 19.320 117.222 19.368 ;
      RECT 0.168 19.704 117.222 19.752 ;
      RECT 0.168 20.088 117.222 20.136 ;
      RECT 0.168 20.472 117.222 20.520 ;
      RECT 0.168 20.856 117.222 20.904 ;
      RECT 0.168 21.240 117.222 21.288 ;
      RECT 0.168 21.624 117.222 21.672 ;
      RECT 0.168 22.008 117.222 22.056 ;
      RECT 0.168 22.392 117.222 22.440 ;
      RECT 0.168 22.776 117.222 22.824 ;
      RECT 0.168 23.160 117.222 23.208 ;
      RECT 0.168 23.544 117.222 23.592 ;
      RECT 0.168 23.928 117.222 23.976 ;
      RECT 0.168 24.312 117.222 24.360 ;
      RECT 0.168 24.696 117.222 24.744 ;
      RECT 0.168 25.080 117.222 25.128 ;
      RECT 0.168 25.464 117.222 25.512 ;
      RECT 0.168 25.848 117.222 25.896 ;
      RECT 0.168 26.232 117.222 26.280 ;
      RECT 0.168 26.616 117.222 26.664 ;
      RECT 0.168 27.000 117.222 27.048 ;
      RECT 0.168 27.384 117.222 27.432 ;
      RECT 0.168 27.768 117.222 27.816 ;
      RECT 0.168 28.152 117.222 28.200 ;
      RECT 0.168 28.536 117.222 28.584 ;
      RECT 0.168 28.920 117.222 28.968 ;
      RECT 0.168 29.304 117.222 29.352 ;
      RECT 0.168 29.688 117.222 29.736 ;
      RECT 0.168 30.072 117.222 30.120 ;
      RECT 0.168 30.456 117.222 30.504 ;
      RECT 0.168 30.840 117.222 30.888 ;
      RECT 0.168 31.224 117.222 31.272 ;
      RECT 0.168 31.608 117.222 31.656 ;
      RECT 0.168 31.992 117.222 32.040 ;
      RECT 0.168 32.376 117.222 32.424 ;
      RECT 0.168 32.760 117.222 32.808 ;
      RECT 0.168 33.144 117.222 33.192 ;
      RECT 0.168 33.528 117.222 33.576 ;
      RECT 0.168 33.912 117.222 33.960 ;
      RECT 0.168 34.296 117.222 34.344 ;
      RECT 0.168 34.680 117.222 34.728 ;
      RECT 0.168 35.064 117.222 35.112 ;
      RECT 0.168 35.448 117.222 35.496 ;
      RECT 0.168 35.832 117.222 35.880 ;
      RECT 0.168 36.216 117.222 36.264 ;
      RECT 0.168 36.600 117.222 36.648 ;
      RECT 0.168 36.984 117.222 37.032 ;
      RECT 0.168 37.368 117.222 37.416 ;
      RECT 0.168 37.752 117.222 37.800 ;
      RECT 0.168 38.136 117.222 38.184 ;
      RECT 0.168 38.520 117.222 38.568 ;
      RECT 0.168 38.904 117.222 38.952 ;
      RECT 0.168 39.288 117.222 39.336 ;
      RECT 0.168 39.672 117.222 39.720 ;
      RECT 0.168 40.056 117.222 40.104 ;
      RECT 0.168 40.440 117.222 40.488 ;
      RECT 0.168 40.824 117.222 40.872 ;
      RECT 0.168 41.208 117.222 41.256 ;
      RECT 0.168 41.592 117.222 41.640 ;
      RECT 0.168 41.976 117.222 42.024 ;
      RECT 0.168 42.360 117.222 42.408 ;
      RECT 0.168 42.744 117.222 42.792 ;
      RECT 0.168 43.128 117.222 43.176 ;
      RECT 0.168 43.512 117.222 43.560 ;
      RECT 0.168 43.896 117.222 43.944 ;
      RECT 0.168 44.280 117.222 44.328 ;
      RECT 0.168 44.664 117.222 44.712 ;
      RECT 0.168 45.048 117.222 45.096 ;
      RECT 0.168 45.432 117.222 45.480 ;
      RECT 0.168 45.816 117.222 45.864 ;
      RECT 0.168 46.200 117.222 46.248 ;
      RECT 0.168 46.584 117.222 46.632 ;
      RECT 0.168 46.968 117.222 47.016 ;
      RECT 0.168 47.352 117.222 47.400 ;
      RECT 0.168 47.736 117.222 47.784 ;
      RECT 0.168 48.120 117.222 48.168 ;
      RECT 0.168 48.504 117.222 48.552 ;
      RECT 0.168 48.888 117.222 48.936 ;
      RECT 0.168 49.272 117.222 49.320 ;
      RECT 0.168 49.656 117.222 49.704 ;
      RECT 0.168 50.040 117.222 50.088 ;
      RECT 0.168 50.424 117.222 50.472 ;
      RECT 0.168 50.808 117.222 50.856 ;
      RECT 0.168 51.192 117.222 51.240 ;
      RECT 0.168 51.576 117.222 51.624 ;
      RECT 0.168 51.960 117.222 52.008 ;
      RECT 0.168 52.344 117.222 52.392 ;
      RECT 0.168 52.728 117.222 52.776 ;
      RECT 0.168 53.112 117.222 53.160 ;
      RECT 0.168 53.496 117.222 53.544 ;
      RECT 0.168 53.880 117.222 53.928 ;
      RECT 0.168 54.264 117.222 54.312 ;
      RECT 0.168 54.648 117.222 54.696 ;
      RECT 0.168 55.032 117.222 55.080 ;
      RECT 0.168 55.416 117.222 55.464 ;
      RECT 0.168 55.800 117.222 55.848 ;
      RECT 0.168 56.184 117.222 56.232 ;
      RECT 0.168 56.568 117.222 56.616 ;
      RECT 0.168 56.952 117.222 57.000 ;
      RECT 0.168 57.336 117.222 57.384 ;
      RECT 0.168 57.720 117.222 57.768 ;
      RECT 0.168 58.104 117.222 58.152 ;
      RECT 0.168 58.488 117.222 58.536 ;
      RECT 0.168 58.872 117.222 58.920 ;
      RECT 0.168 59.256 117.222 59.304 ;
      RECT 0.168 59.640 117.222 59.688 ;
      RECT 0.168 60.024 117.222 60.072 ;
      RECT 0.168 60.408 117.222 60.456 ;
      RECT 0.168 60.792 117.222 60.840 ;
      RECT 0.168 61.176 117.222 61.224 ;
      RECT 0.168 61.560 117.222 61.608 ;
      RECT 0.168 61.944 117.222 61.992 ;
      RECT 0.168 62.328 117.222 62.376 ;
      RECT 0.168 62.712 117.222 62.760 ;
      RECT 0.168 63.096 117.222 63.144 ;
      RECT 0.168 63.480 117.222 63.528 ;
      RECT 0.168 63.864 117.222 63.912 ;
      RECT 0.168 64.248 117.222 64.296 ;
      RECT 0.168 64.632 117.222 64.680 ;
      RECT 0.168 65.016 117.222 65.064 ;
      RECT 0.168 65.400 117.222 65.448 ;
      RECT 0.168 65.784 117.222 65.832 ;
      RECT 0.168 66.168 117.222 66.216 ;
      RECT 0.168 66.552 117.222 66.600 ;
      RECT 0.168 66.936 117.222 66.984 ;
      RECT 0.168 67.320 117.222 67.368 ;
      RECT 0.168 67.704 117.222 67.752 ;
      RECT 0.168 68.088 117.222 68.136 ;
      RECT 0.168 68.472 117.222 68.520 ;
      RECT 0.168 68.856 117.222 68.904 ;
      RECT 0.168 69.240 117.222 69.288 ;
      RECT 0.168 69.624 117.222 69.672 ;
      RECT 0.168 70.008 117.222 70.056 ;
      RECT 0.168 70.392 117.222 70.440 ;
      RECT 0.168 70.776 117.222 70.824 ;
      RECT 0.168 71.160 117.222 71.208 ;
      RECT 0.168 71.544 117.222 71.592 ;
      RECT 0.168 71.928 117.222 71.976 ;
      RECT 0.168 72.312 117.222 72.360 ;
      RECT 0.168 72.696 117.222 72.744 ;
      RECT 0.168 73.080 117.222 73.128 ;
    END
  END VSS
  PIN VDD
    DIRECTION INOUT ;
    USE POWER ;
    PORT
      LAYER M4 ;
      RECT 0.168 0.312 117.222 0.360 ;
      RECT 0.168 0.696 117.222 0.744 ;
      RECT 0.168 1.080 117.222 1.128 ;
      RECT 0.168 1.464 117.222 1.512 ;
      RECT 0.168 1.848 117.222 1.896 ;
      RECT 0.168 2.232 117.222 2.280 ;
      RECT 0.168 2.616 117.222 2.664 ;
      RECT 0.168 3.000 117.222 3.048 ;
      RECT 0.168 3.384 117.222 3.432 ;
      RECT 0.168 3.768 117.222 3.816 ;
      RECT 0.168 4.152 117.222 4.200 ;
      RECT 0.168 4.536 117.222 4.584 ;
      RECT 0.168 4.920 117.222 4.968 ;
      RECT 0.168 5.304 117.222 5.352 ;
      RECT 0.168 5.688 117.222 5.736 ;
      RECT 0.168 6.072 117.222 6.120 ;
      RECT 0.168 6.456 117.222 6.504 ;
      RECT 0.168 6.840 117.222 6.888 ;
      RECT 0.168 7.224 117.222 7.272 ;
      RECT 0.168 7.608 117.222 7.656 ;
      RECT 0.168 7.992 117.222 8.040 ;
      RECT 0.168 8.376 117.222 8.424 ;
      RECT 0.168 8.760 117.222 8.808 ;
      RECT 0.168 9.144 117.222 9.192 ;
      RECT 0.168 9.528 117.222 9.576 ;
      RECT 0.168 9.912 117.222 9.960 ;
      RECT 0.168 10.296 117.222 10.344 ;
      RECT 0.168 10.680 117.222 10.728 ;
      RECT 0.168 11.064 117.222 11.112 ;
      RECT 0.168 11.448 117.222 11.496 ;
      RECT 0.168 11.832 117.222 11.880 ;
      RECT 0.168 12.216 117.222 12.264 ;
      RECT 0.168 12.600 117.222 12.648 ;
      RECT 0.168 12.984 117.222 13.032 ;
      RECT 0.168 13.368 117.222 13.416 ;
      RECT 0.168 13.752 117.222 13.800 ;
      RECT 0.168 14.136 117.222 14.184 ;
      RECT 0.168 14.520 117.222 14.568 ;
      RECT 0.168 14.904 117.222 14.952 ;
      RECT 0.168 15.288 117.222 15.336 ;
      RECT 0.168 15.672 117.222 15.720 ;
      RECT 0.168 16.056 117.222 16.104 ;
      RECT 0.168 16.440 117.222 16.488 ;
      RECT 0.168 16.824 117.222 16.872 ;
      RECT 0.168 17.208 117.222 17.256 ;
      RECT 0.168 17.592 117.222 17.640 ;
      RECT 0.168 17.976 117.222 18.024 ;
      RECT 0.168 18.360 117.222 18.408 ;
      RECT 0.168 18.744 117.222 18.792 ;
      RECT 0.168 19.128 117.222 19.176 ;
      RECT 0.168 19.512 117.222 19.560 ;
      RECT 0.168 19.896 117.222 19.944 ;
      RECT 0.168 20.280 117.222 20.328 ;
      RECT 0.168 20.664 117.222 20.712 ;
      RECT 0.168 21.048 117.222 21.096 ;
      RECT 0.168 21.432 117.222 21.480 ;
      RECT 0.168 21.816 117.222 21.864 ;
      RECT 0.168 22.200 117.222 22.248 ;
      RECT 0.168 22.584 117.222 22.632 ;
      RECT 0.168 22.968 117.222 23.016 ;
      RECT 0.168 23.352 117.222 23.400 ;
      RECT 0.168 23.736 117.222 23.784 ;
      RECT 0.168 24.120 117.222 24.168 ;
      RECT 0.168 24.504 117.222 24.552 ;
      RECT 0.168 24.888 117.222 24.936 ;
      RECT 0.168 25.272 117.222 25.320 ;
      RECT 0.168 25.656 117.222 25.704 ;
      RECT 0.168 26.040 117.222 26.088 ;
      RECT 0.168 26.424 117.222 26.472 ;
      RECT 0.168 26.808 117.222 26.856 ;
      RECT 0.168 27.192 117.222 27.240 ;
      RECT 0.168 27.576 117.222 27.624 ;
      RECT 0.168 27.960 117.222 28.008 ;
      RECT 0.168 28.344 117.222 28.392 ;
      RECT 0.168 28.728 117.222 28.776 ;
      RECT 0.168 29.112 117.222 29.160 ;
      RECT 0.168 29.496 117.222 29.544 ;
      RECT 0.168 29.880 117.222 29.928 ;
      RECT 0.168 30.264 117.222 30.312 ;
      RECT 0.168 30.648 117.222 30.696 ;
      RECT 0.168 31.032 117.222 31.080 ;
      RECT 0.168 31.416 117.222 31.464 ;
      RECT 0.168 31.800 117.222 31.848 ;
      RECT 0.168 32.184 117.222 32.232 ;
      RECT 0.168 32.568 117.222 32.616 ;
      RECT 0.168 32.952 117.222 33.000 ;
      RECT 0.168 33.336 117.222 33.384 ;
      RECT 0.168 33.720 117.222 33.768 ;
      RECT 0.168 34.104 117.222 34.152 ;
      RECT 0.168 34.488 117.222 34.536 ;
      RECT 0.168 34.872 117.222 34.920 ;
      RECT 0.168 35.256 117.222 35.304 ;
      RECT 0.168 35.640 117.222 35.688 ;
      RECT 0.168 36.024 117.222 36.072 ;
      RECT 0.168 36.408 117.222 36.456 ;
      RECT 0.168 36.792 117.222 36.840 ;
      RECT 0.168 37.176 117.222 37.224 ;
      RECT 0.168 37.560 117.222 37.608 ;
      RECT 0.168 37.944 117.222 37.992 ;
      RECT 0.168 38.328 117.222 38.376 ;
      RECT 0.168 38.712 117.222 38.760 ;
      RECT 0.168 39.096 117.222 39.144 ;
      RECT 0.168 39.480 117.222 39.528 ;
      RECT 0.168 39.864 117.222 39.912 ;
      RECT 0.168 40.248 117.222 40.296 ;
      RECT 0.168 40.632 117.222 40.680 ;
      RECT 0.168 41.016 117.222 41.064 ;
      RECT 0.168 41.400 117.222 41.448 ;
      RECT 0.168 41.784 117.222 41.832 ;
      RECT 0.168 42.168 117.222 42.216 ;
      RECT 0.168 42.552 117.222 42.600 ;
      RECT 0.168 42.936 117.222 42.984 ;
      RECT 0.168 43.320 117.222 43.368 ;
      RECT 0.168 43.704 117.222 43.752 ;
      RECT 0.168 44.088 117.222 44.136 ;
      RECT 0.168 44.472 117.222 44.520 ;
      RECT 0.168 44.856 117.222 44.904 ;
      RECT 0.168 45.240 117.222 45.288 ;
      RECT 0.168 45.624 117.222 45.672 ;
      RECT 0.168 46.008 117.222 46.056 ;
      RECT 0.168 46.392 117.222 46.440 ;
      RECT 0.168 46.776 117.222 46.824 ;
      RECT 0.168 47.160 117.222 47.208 ;
      RECT 0.168 47.544 117.222 47.592 ;
      RECT 0.168 47.928 117.222 47.976 ;
      RECT 0.168 48.312 117.222 48.360 ;
      RECT 0.168 48.696 117.222 48.744 ;
      RECT 0.168 49.080 117.222 49.128 ;
      RECT 0.168 49.464 117.222 49.512 ;
      RECT 0.168 49.848 117.222 49.896 ;
      RECT 0.168 50.232 117.222 50.280 ;
      RECT 0.168 50.616 117.222 50.664 ;
      RECT 0.168 51.000 117.222 51.048 ;
      RECT 0.168 51.384 117.222 51.432 ;
      RECT 0.168 51.768 117.222 51.816 ;
      RECT 0.168 52.152 117.222 52.200 ;
      RECT 0.168 52.536 117.222 52.584 ;
      RECT 0.168 52.920 117.222 52.968 ;
      RECT 0.168 53.304 117.222 53.352 ;
      RECT 0.168 53.688 117.222 53.736 ;
      RECT 0.168 54.072 117.222 54.120 ;
      RECT 0.168 54.456 117.222 54.504 ;
      RECT 0.168 54.840 117.222 54.888 ;
      RECT 0.168 55.224 117.222 55.272 ;
      RECT 0.168 55.608 117.222 55.656 ;
      RECT 0.168 55.992 117.222 56.040 ;
      RECT 0.168 56.376 117.222 56.424 ;
      RECT 0.168 56.760 117.222 56.808 ;
      RECT 0.168 57.144 117.222 57.192 ;
      RECT 0.168 57.528 117.222 57.576 ;
      RECT 0.168 57.912 117.222 57.960 ;
      RECT 0.168 58.296 117.222 58.344 ;
      RECT 0.168 58.680 117.222 58.728 ;
      RECT 0.168 59.064 117.222 59.112 ;
      RECT 0.168 59.448 117.222 59.496 ;
      RECT 0.168 59.832 117.222 59.880 ;
      RECT 0.168 60.216 117.222 60.264 ;
      RECT 0.168 60.600 117.222 60.648 ;
      RECT 0.168 60.984 117.222 61.032 ;
      RECT 0.168 61.368 117.222 61.416 ;
      RECT 0.168 61.752 117.222 61.800 ;
      RECT 0.168 62.136 117.222 62.184 ;
      RECT 0.168 62.520 117.222 62.568 ;
      RECT 0.168 62.904 117.222 62.952 ;
      RECT 0.168 63.288 117.222 63.336 ;
      RECT 0.168 63.672 117.222 63.720 ;
      RECT 0.168 64.056 117.222 64.104 ;
      RECT 0.168 64.440 117.222 64.488 ;
      RECT 0.168 64.824 117.222 64.872 ;
      RECT 0.168 65.208 117.222 65.256 ;
      RECT 0.168 65.592 117.222 65.640 ;
      RECT 0.168 65.976 117.222 66.024 ;
      RECT 0.168 66.360 117.222 66.408 ;
      RECT 0.168 66.744 117.222 66.792 ;
      RECT 0.168 67.128 117.222 67.176 ;
      RECT 0.168 67.512 117.222 67.560 ;
      RECT 0.168 67.896 117.222 67.944 ;
      RECT 0.168 68.280 117.222 68.328 ;
      RECT 0.168 68.664 117.222 68.712 ;
      RECT 0.168 69.048 117.222 69.096 ;
      RECT 0.168 69.432 117.222 69.480 ;
      RECT 0.168 69.816 117.222 69.864 ;
      RECT 0.168 70.200 117.222 70.248 ;
      RECT 0.168 70.584 117.222 70.632 ;
      RECT 0.168 70.968 117.222 71.016 ;
      RECT 0.168 71.352 117.222 71.400 ;
      RECT 0.168 71.736 117.222 71.784 ;
      RECT 0.168 72.120 117.222 72.168 ;
      RECT 0.168 72.504 117.222 72.552 ;
      RECT 0.168 72.888 117.222 72.936 ;
      RECT 0.168 73.272 117.222 73.320 ;
    END
  END VDD
  OBS
    LAYER M1 ;
    RECT 0 0 117.390 73.440 ;
    LAYER M2 ;
    RECT 0 0 117.390 73.440 ;
    LAYER M3 ;
    RECT 0 0 117.390 73.440 ;
    LAYER M4 ;
    RECT 0 0 117.390 73.440 ;
  END
END fakeram7_256x256

END LIBRARY
